VERSION 5.8 ;
BUSBITCHARS "[]" ;
DIVIDERCHAR "/" ;
UNITS
    DATABASE MICRONS 1000 ;
END UNITS

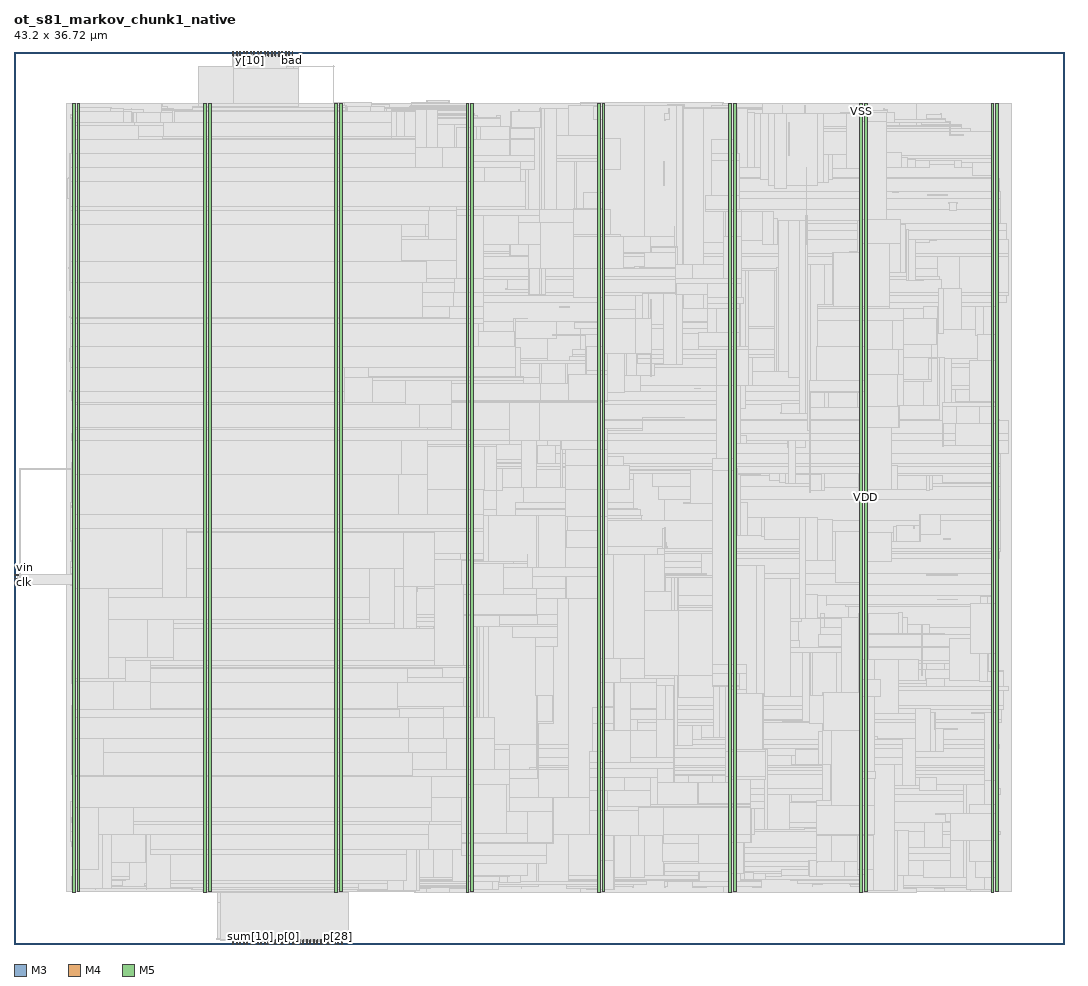
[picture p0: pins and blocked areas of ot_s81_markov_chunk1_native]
MACRO ot_s81_markov_chunk1_native
  FOREIGN ot_s81_markov_chunk1_native 0 0 ;
  CLASS BLOCK ;
  SIZE 43.2 BY 36.72 ;
  PIN bad
    DIRECTION OUTPUT ;
    USE SIGNAL ;
    PORT
      LAYER M3 ;
        RECT  11.448 36.576 11.466 36.72 ;
    END
  END bad
  PIN clk
    DIRECTION INPUT ;
    USE SIGNAL ;
    PORT
      LAYER M4 ;
        RECT  0 14.88 0.192 14.904 ;
    END
  END clk
  PIN p[0]
    DIRECTION INPUT ;
    USE SIGNAL ;
    PORT
      LAYER M3 ;
        RECT  11.304 0 11.322 0.144 ;
    END
  END p[0]
  PIN p[10]
    DIRECTION INPUT ;
    USE SIGNAL ;
    PORT
      LAYER M3 ;
        RECT  12.024 0 12.042 0.144 ;
    END
  END p[10]
  PIN p[11]
    DIRECTION INPUT ;
    USE SIGNAL ;
    PORT
      LAYER M5 ;
        RECT  12.048 0 12.072 0.192 ;
    END
  END p[11]
  PIN p[12]
    DIRECTION INPUT ;
    USE SIGNAL ;
    PORT
      LAYER M3 ;
        RECT  12.168 0 12.186 0.144 ;
    END
  END p[12]
  PIN p[13]
    DIRECTION INPUT ;
    USE SIGNAL ;
    PORT
      LAYER M5 ;
        RECT  12.192 0 12.216 0.192 ;
    END
  END p[13]
  PIN p[14]
    DIRECTION INPUT ;
    USE SIGNAL ;
    PORT
      LAYER M3 ;
        RECT  12.312 0 12.33 0.144 ;
    END
  END p[14]
  PIN p[15]
    DIRECTION INPUT ;
    USE SIGNAL ;
    PORT
      LAYER M5 ;
        RECT  12.336 0 12.36 0.192 ;
    END
  END p[15]
  PIN p[16]
    DIRECTION INPUT ;
    USE SIGNAL ;
    PORT
      LAYER M3 ;
        RECT  12.456 0 12.474 0.144 ;
    END
  END p[16]
  PIN p[17]
    DIRECTION INPUT ;
    USE SIGNAL ;
    PORT
      LAYER M5 ;
        RECT  12.48 0 12.504 0.192 ;
    END
  END p[17]
  PIN p[18]
    DIRECTION INPUT ;
    USE SIGNAL ;
    PORT
      LAYER M3 ;
        RECT  12.6 0 12.618 0.144 ;
    END
  END p[18]
  PIN p[19]
    DIRECTION INPUT ;
    USE SIGNAL ;
    PORT
      LAYER M5 ;
        RECT  12.624 0 12.648 0.192 ;
    END
  END p[19]
  PIN p[1]
    DIRECTION INPUT ;
    USE SIGNAL ;
    PORT
      LAYER M5 ;
        RECT  11.328 0 11.352 0.192 ;
    END
  END p[1]
  PIN p[20]
    DIRECTION INPUT ;
    USE SIGNAL ;
    PORT
      LAYER M3 ;
        RECT  12.744 0 12.762 0.144 ;
    END
  END p[20]
  PIN p[21]
    DIRECTION INPUT ;
    USE SIGNAL ;
    PORT
      LAYER M5 ;
        RECT  12.768 0 12.792 0.192 ;
    END
  END p[21]
  PIN p[22]
    DIRECTION INPUT ;
    USE SIGNAL ;
    PORT
      LAYER M3 ;
        RECT  12.888 0 12.906 0.144 ;
    END
  END p[22]
  PIN p[23]
    DIRECTION INPUT ;
    USE SIGNAL ;
    PORT
      LAYER M5 ;
        RECT  12.912 0 12.936 0.192 ;
    END
  END p[23]
  PIN p[24]
    DIRECTION INPUT ;
    USE SIGNAL ;
    PORT
      LAYER M3 ;
        RECT  13.032 0 13.05 0.144 ;
    END
  END p[24]
  PIN p[25]
    DIRECTION INPUT ;
    USE SIGNAL ;
    PORT
      LAYER M5 ;
        RECT  13.056 0 13.08 0.192 ;
    END
  END p[25]
  PIN p[26]
    DIRECTION INPUT ;
    USE SIGNAL ;
    PORT
      LAYER M3 ;
        RECT  13.176 0 13.194 0.144 ;
    END
  END p[26]
  PIN p[27]
    DIRECTION INPUT ;
    USE SIGNAL ;
    PORT
      LAYER M5 ;
        RECT  13.2 0 13.224 0.192 ;
    END
  END p[27]
  PIN p[28]
    DIRECTION INPUT ;
    USE SIGNAL ;
    PORT
      LAYER M3 ;
        RECT  13.32 0 13.338 0.144 ;
    END
  END p[28]
  PIN p[29]
    DIRECTION INPUT ;
    USE SIGNAL ;
    PORT
      LAYER M5 ;
        RECT  13.344 0 13.368 0.192 ;
    END
  END p[29]
  PIN p[2]
    DIRECTION INPUT ;
    USE SIGNAL ;
    PORT
      LAYER M3 ;
        RECT  11.448 0 11.466 0.144 ;
    END
  END p[2]
  PIN p[30]
    DIRECTION INPUT ;
    USE SIGNAL ;
    PORT
      LAYER M3 ;
        RECT  13.464 0 13.482 0.144 ;
    END
  END p[30]
  PIN p[31]
    DIRECTION INPUT ;
    USE SIGNAL ;
    PORT
      LAYER M5 ;
        RECT  13.488 0 13.512 0.192 ;
    END
  END p[31]
  PIN p[3]
    DIRECTION INPUT ;
    USE SIGNAL ;
    PORT
      LAYER M5 ;
        RECT  11.472 0 11.496 0.192 ;
    END
  END p[3]
  PIN p[4]
    DIRECTION INPUT ;
    USE SIGNAL ;
    PORT
      LAYER M3 ;
        RECT  11.592 0 11.61 0.144 ;
    END
  END p[4]
  PIN p[5]
    DIRECTION INPUT ;
    USE SIGNAL ;
    PORT
      LAYER M5 ;
        RECT  11.616 0 11.64 0.192 ;
    END
  END p[5]
  PIN p[6]
    DIRECTION INPUT ;
    USE SIGNAL ;
    PORT
      LAYER M3 ;
        RECT  11.736 0 11.754 0.144 ;
    END
  END p[6]
  PIN p[7]
    DIRECTION INPUT ;
    USE SIGNAL ;
    PORT
      LAYER M5 ;
        RECT  11.76 0 11.784 0.192 ;
    END
  END p[7]
  PIN p[8]
    DIRECTION INPUT ;
    USE SIGNAL ;
    PORT
      LAYER M3 ;
        RECT  11.88 0 11.898 0.144 ;
    END
  END p[8]
  PIN p[9]
    DIRECTION INPUT ;
    USE SIGNAL ;
    PORT
      LAYER M5 ;
        RECT  11.904 0 11.928 0.192 ;
    END
  END p[9]
  PIN rst_n
    DIRECTION INPUT ;
    USE SIGNAL ;
    PORT
      LAYER M4 ;
        RECT  0 15.024 0.192 15.048 ;
    END
  END rst_n
  PIN sum[0]
    DIRECTION INPUT ;
    USE SIGNAL ;
    PORT
      LAYER M3 ;
        RECT  9 0 9.018 0.144 ;
    END
  END sum[0]
  PIN sum[10]
    DIRECTION INPUT ;
    USE SIGNAL ;
    PORT
      LAYER M3 ;
        RECT  9.72 0 9.738 0.144 ;
    END
  END sum[10]
  PIN sum[11]
    DIRECTION INPUT ;
    USE SIGNAL ;
    PORT
      LAYER M5 ;
        RECT  9.744 0 9.768 0.192 ;
    END
  END sum[11]
  PIN sum[12]
    DIRECTION INPUT ;
    USE SIGNAL ;
    PORT
      LAYER M3 ;
        RECT  9.864 0 9.882 0.144 ;
    END
  END sum[12]
  PIN sum[13]
    DIRECTION INPUT ;
    USE SIGNAL ;
    PORT
      LAYER M5 ;
        RECT  9.888 0 9.912 0.192 ;
    END
  END sum[13]
  PIN sum[14]
    DIRECTION INPUT ;
    USE SIGNAL ;
    PORT
      LAYER M3 ;
        RECT  10.008 0 10.026 0.144 ;
    END
  END sum[14]
  PIN sum[15]
    DIRECTION INPUT ;
    USE SIGNAL ;
    PORT
      LAYER M5 ;
        RECT  10.032 0 10.056 0.192 ;
    END
  END sum[15]
  PIN sum[16]
    DIRECTION INPUT ;
    USE SIGNAL ;
    PORT
      LAYER M3 ;
        RECT  10.152 0 10.17 0.144 ;
    END
  END sum[16]
  PIN sum[17]
    DIRECTION INPUT ;
    USE SIGNAL ;
    PORT
      LAYER M5 ;
        RECT  10.176 0 10.2 0.192 ;
    END
  END sum[17]
  PIN sum[18]
    DIRECTION INPUT ;
    USE SIGNAL ;
    PORT
      LAYER M3 ;
        RECT  10.296 0 10.314 0.144 ;
    END
  END sum[18]
  PIN sum[19]
    DIRECTION INPUT ;
    USE SIGNAL ;
    PORT
      LAYER M5 ;
        RECT  10.32 0 10.344 0.192 ;
    END
  END sum[19]
  PIN sum[1]
    DIRECTION INPUT ;
    USE SIGNAL ;
    PORT
      LAYER M5 ;
        RECT  9.024 0 9.048 0.192 ;
    END
  END sum[1]
  PIN sum[20]
    DIRECTION INPUT ;
    USE SIGNAL ;
    PORT
      LAYER M3 ;
        RECT  10.44 0 10.458 0.144 ;
    END
  END sum[20]
  PIN sum[21]
    DIRECTION INPUT ;
    USE SIGNAL ;
    PORT
      LAYER M5 ;
        RECT  10.464 0 10.488 0.192 ;
    END
  END sum[21]
  PIN sum[22]
    DIRECTION INPUT ;
    USE SIGNAL ;
    PORT
      LAYER M3 ;
        RECT  10.584 0 10.602 0.144 ;
    END
  END sum[22]
  PIN sum[23]
    DIRECTION INPUT ;
    USE SIGNAL ;
    PORT
      LAYER M5 ;
        RECT  10.608 0 10.632 0.192 ;
    END
  END sum[23]
  PIN sum[24]
    DIRECTION INPUT ;
    USE SIGNAL ;
    PORT
      LAYER M3 ;
        RECT  10.728 0 10.746 0.144 ;
    END
  END sum[24]
  PIN sum[25]
    DIRECTION INPUT ;
    USE SIGNAL ;
    PORT
      LAYER M5 ;
        RECT  10.752 0 10.776 0.192 ;
    END
  END sum[25]
  PIN sum[26]
    DIRECTION INPUT ;
    USE SIGNAL ;
    PORT
      LAYER M3 ;
        RECT  10.872 0 10.89 0.144 ;
    END
  END sum[26]
  PIN sum[27]
    DIRECTION INPUT ;
    USE SIGNAL ;
    PORT
      LAYER M5 ;
        RECT  10.896 0 10.92 0.192 ;
    END
  END sum[27]
  PIN sum[28]
    DIRECTION INPUT ;
    USE SIGNAL ;
    PORT
      LAYER M3 ;
        RECT  11.016 0 11.034 0.144 ;
    END
  END sum[28]
  PIN sum[29]
    DIRECTION INPUT ;
    USE SIGNAL ;
    PORT
      LAYER M5 ;
        RECT  11.04 0 11.064 0.192 ;
    END
  END sum[29]
  PIN sum[2]
    DIRECTION INPUT ;
    USE SIGNAL ;
    PORT
      LAYER M3 ;
        RECT  9.144 0 9.162 0.144 ;
    END
  END sum[2]
  PIN sum[30]
    DIRECTION INPUT ;
    USE SIGNAL ;
    PORT
      LAYER M3 ;
        RECT  11.16 0 11.178 0.144 ;
    END
  END sum[30]
  PIN sum[31]
    DIRECTION INPUT ;
    USE SIGNAL ;
    PORT
      LAYER M5 ;
        RECT  11.184 0 11.208 0.192 ;
    END
  END sum[31]
  PIN sum[3]
    DIRECTION INPUT ;
    USE SIGNAL ;
    PORT
      LAYER M5 ;
        RECT  9.168 0 9.192 0.192 ;
    END
  END sum[3]
  PIN sum[4]
    DIRECTION INPUT ;
    USE SIGNAL ;
    PORT
      LAYER M3 ;
        RECT  9.288 0 9.306 0.144 ;
    END
  END sum[4]
  PIN sum[5]
    DIRECTION INPUT ;
    USE SIGNAL ;
    PORT
      LAYER M5 ;
        RECT  9.312 0 9.336 0.192 ;
    END
  END sum[5]
  PIN sum[6]
    DIRECTION INPUT ;
    USE SIGNAL ;
    PORT
      LAYER M3 ;
        RECT  9.432 0 9.45 0.144 ;
    END
  END sum[6]
  PIN sum[7]
    DIRECTION INPUT ;
    USE SIGNAL ;
    PORT
      LAYER M5 ;
        RECT  9.456 0 9.48 0.192 ;
    END
  END sum[7]
  PIN sum[8]
    DIRECTION INPUT ;
    USE SIGNAL ;
    PORT
      LAYER M3 ;
        RECT  9.576 0 9.594 0.144 ;
    END
  END sum[8]
  PIN sum[9]
    DIRECTION INPUT ;
    USE SIGNAL ;
    PORT
      LAYER M5 ;
        RECT  9.6 0 9.624 0.192 ;
    END
  END sum[9]
  PIN vin
    DIRECTION INPUT ;
    USE SIGNAL ;
    PORT
      LAYER M4 ;
        RECT  0 15.168 0.192 15.192 ;
    END
  END vin
  PIN vout
    DIRECTION OUTPUT ;
    USE SIGNAL ;
    PORT
      LAYER M3 ;
        RECT  11.304 36.576 11.322 36.72 ;
    END
  END vout
  PIN y[0]
    DIRECTION OUTPUT ;
    USE SIGNAL ;
    PORT
      LAYER M3 ;
        RECT  9 36.576 9.018 36.72 ;
    END
  END y[0]
  PIN y[10]
    DIRECTION OUTPUT ;
    USE SIGNAL ;
    PORT
      LAYER M3 ;
        RECT  9.72 36.576 9.738 36.72 ;
    END
  END y[10]
  PIN y[11]
    DIRECTION OUTPUT ;
    USE SIGNAL ;
    PORT
      LAYER M5 ;
        RECT  9.744 36.528 9.768 36.72 ;
    END
  END y[11]
  PIN y[12]
    DIRECTION OUTPUT ;
    USE SIGNAL ;
    PORT
      LAYER M3 ;
        RECT  9.864 36.576 9.882 36.72 ;
    END
  END y[12]
  PIN y[13]
    DIRECTION OUTPUT ;
    USE SIGNAL ;
    PORT
      LAYER M5 ;
        RECT  9.888 36.528 9.912 36.72 ;
    END
  END y[13]
  PIN y[14]
    DIRECTION OUTPUT ;
    USE SIGNAL ;
    PORT
      LAYER M3 ;
        RECT  10.008 36.576 10.026 36.72 ;
    END
  END y[14]
  PIN y[15]
    DIRECTION OUTPUT ;
    USE SIGNAL ;
    PORT
      LAYER M5 ;
        RECT  10.032 36.528 10.056 36.72 ;
    END
  END y[15]
  PIN y[16]
    DIRECTION OUTPUT ;
    USE SIGNAL ;
    PORT
      LAYER M3 ;
        RECT  10.152 36.576 10.17 36.72 ;
    END
  END y[16]
  PIN y[17]
    DIRECTION OUTPUT ;
    USE SIGNAL ;
    PORT
      LAYER M5 ;
        RECT  10.176 36.528 10.2 36.72 ;
    END
  END y[17]
  PIN y[18]
    DIRECTION OUTPUT ;
    USE SIGNAL ;
    PORT
      LAYER M3 ;
        RECT  10.296 36.576 10.314 36.72 ;
    END
  END y[18]
  PIN y[19]
    DIRECTION OUTPUT ;
    USE SIGNAL ;
    PORT
      LAYER M5 ;
        RECT  10.32 36.528 10.344 36.72 ;
    END
  END y[19]
  PIN y[1]
    DIRECTION OUTPUT ;
    USE SIGNAL ;
    PORT
      LAYER M5 ;
        RECT  9.024 36.528 9.048 36.72 ;
    END
  END y[1]
  PIN y[20]
    DIRECTION OUTPUT ;
    USE SIGNAL ;
    PORT
      LAYER M3 ;
        RECT  10.44 36.576 10.458 36.72 ;
    END
  END y[20]
  PIN y[21]
    DIRECTION OUTPUT ;
    USE SIGNAL ;
    PORT
      LAYER M5 ;
        RECT  10.464 36.528 10.488 36.72 ;
    END
  END y[21]
  PIN y[22]
    DIRECTION OUTPUT ;
    USE SIGNAL ;
    PORT
      LAYER M3 ;
        RECT  10.584 36.576 10.602 36.72 ;
    END
  END y[22]
  PIN y[23]
    DIRECTION OUTPUT ;
    USE SIGNAL ;
    PORT
      LAYER M5 ;
        RECT  10.608 36.528 10.632 36.72 ;
    END
  END y[23]
  PIN y[24]
    DIRECTION OUTPUT ;
    USE SIGNAL ;
    PORT
      LAYER M3 ;
        RECT  10.728 36.576 10.746 36.72 ;
    END
  END y[24]
  PIN y[25]
    DIRECTION OUTPUT ;
    USE SIGNAL ;
    PORT
      LAYER M5 ;
        RECT  10.752 36.528 10.776 36.72 ;
    END
  END y[25]
  PIN y[26]
    DIRECTION OUTPUT ;
    USE SIGNAL ;
    PORT
      LAYER M3 ;
        RECT  10.872 36.576 10.89 36.72 ;
    END
  END y[26]
  PIN y[27]
    DIRECTION OUTPUT ;
    USE SIGNAL ;
    PORT
      LAYER M5 ;
        RECT  10.896 36.528 10.92 36.72 ;
    END
  END y[27]
  PIN y[28]
    DIRECTION OUTPUT ;
    USE SIGNAL ;
    PORT
      LAYER M3 ;
        RECT  11.016 36.576 11.034 36.72 ;
    END
  END y[28]
  PIN y[29]
    DIRECTION OUTPUT ;
    USE SIGNAL ;
    PORT
      LAYER M5 ;
        RECT  11.04 36.528 11.064 36.72 ;
    END
  END y[29]
  PIN y[2]
    DIRECTION OUTPUT ;
    USE SIGNAL ;
    PORT
      LAYER M3 ;
        RECT  9.144 36.576 9.162 36.72 ;
    END
  END y[2]
  PIN y[30]
    DIRECTION OUTPUT ;
    USE SIGNAL ;
    PORT
      LAYER M3 ;
        RECT  11.16 36.576 11.178 36.72 ;
    END
  END y[30]
  PIN y[31]
    DIRECTION OUTPUT ;
    USE SIGNAL ;
    PORT
      LAYER M5 ;
        RECT  11.184 36.528 11.208 36.72 ;
    END
  END y[31]
  PIN y[3]
    DIRECTION OUTPUT ;
    USE SIGNAL ;
    PORT
      LAYER M5 ;
        RECT  9.168 36.528 9.192 36.72 ;
    END
  END y[3]
  PIN y[4]
    DIRECTION OUTPUT ;
    USE SIGNAL ;
    PORT
      LAYER M3 ;
        RECT  9.288 36.576 9.306 36.72 ;
    END
  END y[4]
  PIN y[5]
    DIRECTION OUTPUT ;
    USE SIGNAL ;
    PORT
      LAYER M5 ;
        RECT  9.312 36.528 9.336 36.72 ;
    END
  END y[5]
  PIN y[6]
    DIRECTION OUTPUT ;
    USE SIGNAL ;
    PORT
      LAYER M3 ;
        RECT  9.432 36.576 9.45 36.72 ;
    END
  END y[6]
  PIN y[7]
    DIRECTION OUTPUT ;
    USE SIGNAL ;
    PORT
      LAYER M5 ;
        RECT  9.456 36.528 9.48 36.72 ;
    END
  END y[7]
  PIN y[8]
    DIRECTION OUTPUT ;
    USE SIGNAL ;
    PORT
      LAYER M3 ;
        RECT  9.576 36.576 9.594 36.72 ;
    END
  END y[8]
  PIN y[9]
    DIRECTION OUTPUT ;
    USE SIGNAL ;
    PORT
      LAYER M5 ;
        RECT  9.6 36.528 9.624 36.72 ;
    END
  END y[9]
  PIN VDD
    DIRECTION INOUT ;
    USE POWER ;
    PORT
      LAYER M5 ;
        RECT  40.392 2.151 40.512 34.569 ;
        RECT  34.992 2.151 35.112 34.569 ;
        RECT  29.592 2.151 29.712 34.569 ;
        RECT  24.192 2.151 24.312 34.569 ;
        RECT  18.792 2.151 18.912 34.569 ;
        RECT  13.392 2.151 13.512 34.569 ;
        RECT  7.992 2.151 8.112 34.569 ;
        RECT  2.592 2.151 2.712 34.569 ;
    END
  END VDD
  PIN VSS
    DIRECTION INOUT ;
    USE GROUND ;
    PORT
      LAYER M5 ;
        RECT  40.2 2.137 40.32 34.583 ;
        RECT  34.8 2.137 34.92 34.583 ;
        RECT  29.4 2.137 29.52 34.583 ;
        RECT  24 2.137 24.12 34.583 ;
        RECT  18.6 2.137 18.72 34.583 ;
        RECT  13.2 2.137 13.32 34.583 ;
        RECT  7.8 2.137 7.92 34.583 ;
        RECT  2.4 2.137 2.52 34.583 ;
    END
  END VSS
  # OT_OBS_CLOSED layer=M5 d_um=1.536 added=148
  OBS
    LAYER RVTN ;
     RECT  2.16 2.16 41.04 2.295 ;
     RECT  2.16 2.565 41.04 2.835 ;
     RECT  2.16 3.105 41.04 3.375 ;
     RECT  2.16 3.645 41.04 3.915 ;
     RECT  2.16 4.185 41.04 4.455 ;
     RECT  2.16 4.725 41.04 4.995 ;
     RECT  2.16 5.265 41.04 5.535 ;
     RECT  2.16 5.805 41.04 6.075 ;
     RECT  2.16 6.345 41.04 6.615 ;
     RECT  2.16 6.885 41.04 7.155 ;
     RECT  2.16 7.425 41.04 7.695 ;
     RECT  2.16 7.965 41.04 8.235 ;
     RECT  2.16 8.505 41.04 8.775 ;
     RECT  2.16 9.045 41.04 9.315 ;
     RECT  2.16 9.585 41.04 9.855 ;
     RECT  2.16 10.125 41.04 10.395 ;
     RECT  2.16 10.665 41.04 10.935 ;
     RECT  2.16 11.205 41.04 11.475 ;
     RECT  2.16 11.745 41.04 12.015 ;
     RECT  2.16 12.285 41.04 12.555 ;
     RECT  2.16 12.825 41.04 13.095 ;
     RECT  2.16 13.365 41.04 13.635 ;
     RECT  2.16 13.905 41.04 14.175 ;
     RECT  2.16 14.445 41.04 14.715 ;
     RECT  2.16 14.985 41.04 15.255 ;
     RECT  2.16 15.525 41.04 15.795 ;
     RECT  2.16 16.065 41.04 16.335 ;
     RECT  2.16 16.605 41.04 16.875 ;
     RECT  2.16 17.145 41.04 17.415 ;
     RECT  2.16 17.685 41.04 17.955 ;
     RECT  2.16 18.225 41.04 18.495 ;
     RECT  2.16 18.765 41.04 19.035 ;
     RECT  2.16 19.305 41.04 19.575 ;
     RECT  2.16 19.845 41.04 20.115 ;
     RECT  2.16 20.385 41.04 20.655 ;
     RECT  2.16 20.925 41.04 21.195 ;
     RECT  2.16 21.465 41.04 21.735 ;
     RECT  2.16 22.005 41.04 22.275 ;
     RECT  2.16 22.545 41.04 22.815 ;
     RECT  2.16 23.085 41.04 23.355 ;
     RECT  2.16 23.625 41.04 23.895 ;
     RECT  2.16 24.165 41.04 24.435 ;
     RECT  2.16 24.705 41.04 24.975 ;
     RECT  2.16 25.245 41.04 25.515 ;
     RECT  2.16 25.785 41.04 26.055 ;
     RECT  2.16 26.325 41.04 26.595 ;
     RECT  2.16 26.865 41.04 27.135 ;
     RECT  2.16 27.405 41.04 27.675 ;
     RECT  2.16 27.945 41.04 28.215 ;
     RECT  2.16 28.485 41.04 28.755 ;
     RECT  2.16 29.025 41.04 29.295 ;
     RECT  2.16 29.565 41.04 29.835 ;
     RECT  2.16 30.105 41.04 30.375 ;
     RECT  2.16 30.645 41.04 30.915 ;
     RECT  2.16 31.185 41.04 31.455 ;
     RECT  2.16 31.725 41.04 31.995 ;
     RECT  2.16 32.265 41.04 32.535 ;
     RECT  2.16 32.805 41.04 33.075 ;
     RECT  2.16 33.345 41.04 33.615 ;
     RECT  2.16 33.885 41.04 34.155 ;
     RECT  2.16 34.425 41.04 34.56 ;
    LAYER RVTP ;
     RECT  2.16 2.295 41.04 2.565 ;
     RECT  2.16 2.835 41.04 3.105 ;
     RECT  2.16 3.375 41.04 3.645 ;
     RECT  2.16 3.915 41.04 4.185 ;
     RECT  2.16 4.455 41.04 4.725 ;
     RECT  2.16 4.995 41.04 5.265 ;
     RECT  2.16 5.535 41.04 5.805 ;
     RECT  2.16 6.075 41.04 6.345 ;
     RECT  2.16 6.615 41.04 6.885 ;
     RECT  2.16 7.155 41.04 7.425 ;
     RECT  2.16 7.695 41.04 7.965 ;
     RECT  2.16 8.235 41.04 8.505 ;
     RECT  2.16 8.775 41.04 9.045 ;
     RECT  2.16 9.315 41.04 9.585 ;
     RECT  2.16 9.855 41.04 10.125 ;
     RECT  2.16 10.395 41.04 10.665 ;
     RECT  2.16 10.935 41.04 11.205 ;
     RECT  2.16 11.475 41.04 11.745 ;
     RECT  2.16 12.015 41.04 12.285 ;
     RECT  2.16 12.555 41.04 12.825 ;
     RECT  2.16 13.095 41.04 13.365 ;
     RECT  2.16 13.635 41.04 13.905 ;
     RECT  2.16 14.175 41.04 14.445 ;
     RECT  2.16 14.715 41.04 14.985 ;
     RECT  2.16 15.255 41.04 15.525 ;
     RECT  2.16 15.795 41.04 16.065 ;
     RECT  2.16 16.335 41.04 16.605 ;
     RECT  2.16 16.875 41.04 17.145 ;
     RECT  2.16 17.415 41.04 17.685 ;
     RECT  2.16 17.955 41.04 18.225 ;
     RECT  2.16 18.495 41.04 18.765 ;
     RECT  2.16 19.035 41.04 19.305 ;
     RECT  2.16 19.575 41.04 19.845 ;
     RECT  2.16 20.115 41.04 20.385 ;
     RECT  2.16 20.655 41.04 20.925 ;
     RECT  2.16 21.195 41.04 21.465 ;
     RECT  2.16 21.735 41.04 22.005 ;
     RECT  2.16 22.275 41.04 22.545 ;
     RECT  2.16 22.815 41.04 23.085 ;
     RECT  2.16 23.355 41.04 23.625 ;
     RECT  2.16 23.895 41.04 24.165 ;
     RECT  2.16 24.435 41.04 24.705 ;
     RECT  2.16 24.975 41.04 25.245 ;
     RECT  2.16 25.515 41.04 25.785 ;
     RECT  2.16 26.055 41.04 26.325 ;
     RECT  2.16 26.595 41.04 26.865 ;
     RECT  2.16 27.135 41.04 27.405 ;
     RECT  2.16 27.675 41.04 27.945 ;
     RECT  2.16 28.215 41.04 28.485 ;
     RECT  2.16 28.755 41.04 29.025 ;
     RECT  2.16 29.295 41.04 29.565 ;
     RECT  2.16 29.835 41.04 30.105 ;
     RECT  2.16 30.375 41.04 30.645 ;
     RECT  2.16 30.915 41.04 31.185 ;
     RECT  2.16 31.455 41.04 31.725 ;
     RECT  2.16 31.995 41.04 32.265 ;
     RECT  2.16 32.535 41.04 32.805 ;
     RECT  2.16 33.075 41.04 33.345 ;
     RECT  2.16 33.615 41.04 33.885 ;
     RECT  2.16 34.155 41.04 34.425 ;
    LAYER M1 ;
     RECT  2.16 2.151 41.04 34.569 ;
    LAYER M2 ;
     RECT  2.16 2.151 8.203 34.569 ;
     RECT  8.203 2.106 9.355 34.569 ;
     RECT  9.355 1.728 9.463 34.569 ;
     RECT  9.463 1.728 9.599 34.794 ;
     RECT  9.599 1.728 9.815 34.569 ;
     RECT  9.815 2.151 10.579 34.569 ;
     RECT  10.579 0.144 10.679 0.162 ;
     RECT  10.579 2.151 10.823 34.794 ;
     RECT  12.163 0.144 12.883 0.162 ;
     RECT  12.883 0.144 12.983 0.63 ;
     RECT  12.983 0.144 13.487 0.162 ;
     RECT  10.823 2.151 13.567 34.569 ;
     RECT  13.567 2.151 14.711 34.614 ;
     RECT  14.711 2.151 16.339 34.569 ;
     RECT  16.339 2.151 16.483 34.614 ;
     RECT  16.483 2.106 16.987 34.614 ;
     RECT  16.987 2.106 17.915 34.686 ;
     RECT  17.915 2.106 23.323 34.569 ;
     RECT  23.323 2.106 29.183 34.614 ;
     RECT  29.183 2.106 37.139 34.569 ;
     RECT  37.139 2.151 41.04 34.569 ;
    LAYER M3 ;
     RECT  9 0.108 13.482 0.167 ;
     RECT  9 0.167 13.41 0.187 ;
     RECT  8.352 0.187 13.41 1.723 ;
     RECT  8.352 1.723 13.662 2.101 ;
     RECT  8.208 2.101 13.662 2.143 ;
     RECT  7.815 2.143 13.662 2.155 ;
     RECT  7.815 2.155 13.914 2.191 ;
     RECT  16.488 2.101 16.506 2.191 ;
     RECT  34.815 2.143 34.905 2.191 ;
     RECT  40.215 2.143 40.305 2.191 ;
     RECT  16.2 2.191 16.506 2.203 ;
     RECT  2.415 2.143 2.505 2.227 ;
     RECT  15.516 2.203 16.686 2.227 ;
     RECT  24.015 2.143 24.105 2.227 ;
     RECT  34.815 2.191 35.442 2.227 ;
     RECT  36.324 2.203 36.342 2.227 ;
     RECT  7.74 2.191 14.634 2.251 ;
     RECT  39.348 2.191 39.366 2.251 ;
     RECT  40.176 2.191 40.305 2.251 ;
     RECT  34.815 2.227 36.342 2.255 ;
     RECT  15.372 2.227 16.686 2.263 ;
     RECT  18.615 2.143 18.705 2.263 ;
     RECT  23.544 2.227 24.678 2.263 ;
     RECT  37.116 2.101 37.134 2.263 ;
     RECT  38.268 2.191 38.286 2.263 ;
     RECT  7.308 2.251 14.634 2.299 ;
     RECT  15.372 2.263 17.118 2.335 ;
     RECT  17.964 2.263 18.705 2.335 ;
     RECT  36.612 2.263 37.134 2.335 ;
     RECT  37.872 2.263 38.286 2.335 ;
     RECT  39.204 2.251 40.305 2.335 ;
     RECT  4.428 2.299 4.446 2.347 ;
     RECT  5.436 2.227 5.454 2.347 ;
     RECT  6.624 2.299 14.634 2.347 ;
     RECT  3.348 2.227 3.366 2.371 ;
     RECT  4.248 2.347 4.446 2.371 ;
     RECT  5.364 2.347 5.454 2.371 ;
     RECT  6.3 2.347 14.634 2.371 ;
     RECT  15.372 2.335 18.705 2.371 ;
     RECT  19.908 2.227 19.926 2.371 ;
     RECT  20.88 2.299 20.898 2.371 ;
     RECT  22.716 2.263 24.678 2.371 ;
     RECT  25.452 2.335 25.47 2.371 ;
     RECT  26.784 2.335 26.802 2.371 ;
     RECT  27.9 2.335 28.494 2.371 ;
     RECT  29.415 2.143 29.505 2.371 ;
     RECT  30.384 2.335 30.762 2.371 ;
     RECT  34.815 2.255 35.766 2.371 ;
     RECT  2.376 2.227 2.505 2.413 ;
     RECT  3.348 2.371 4.446 2.413 ;
     RECT  5.364 2.371 18.705 2.413 ;
     RECT  36.612 2.335 40.305 2.413 ;
     RECT  19.908 2.371 21.582 2.461 ;
     RECT  22.716 2.371 25.47 2.461 ;
     RECT  32.832 2.371 32.85 2.461 ;
     RECT  34.416 2.371 35.766 2.461 ;
     RECT  5.364 2.413 18.897 2.489 ;
     RECT  32.832 2.461 33.246 2.497 ;
     RECT  34.38 2.461 35.766 2.497 ;
     RECT  26.784 2.371 26.874 2.569 ;
     RECT  27.9 2.371 30.762 2.569 ;
     RECT  5.472 2.489 18.897 2.587 ;
     RECT  19.908 2.461 26.01 2.587 ;
     RECT  2.376 2.413 4.446 2.605 ;
     RECT  5.472 2.587 26.01 2.605 ;
     RECT  26.784 2.569 30.762 2.605 ;
     RECT  32.256 2.497 35.766 2.605 ;
     RECT  5.472 2.605 30.762 2.635 ;
     RECT  2.376 2.605 4.59 2.641 ;
     RECT  5.472 2.635 30.906 2.641 ;
     RECT  31.932 2.605 35.766 2.641 ;
     RECT  2.376 2.641 4.734 2.759 ;
     RECT  5.472 2.641 35.766 3.001 ;
     RECT  5.472 3.001 35.802 3.181 ;
     RECT  36.612 2.413 40.497 3.181 ;
     RECT  2.415 2.759 4.734 3.379 ;
     RECT  5.472 3.181 40.497 3.379 ;
     RECT  2.415 3.379 40.497 3.725 ;
     RECT  5.904 3.725 40.497 3.983 ;
     RECT  2.415 3.725 5.166 3.991 ;
     RECT  2.376 3.991 5.166 4.225 ;
     RECT  38.196 3.983 40.497 4.495 ;
     RECT  2.34 4.225 5.166 4.621 ;
     RECT  5.904 3.983 37.458 4.621 ;
     RECT  38.196 4.495 40.59 4.649 ;
     RECT  2.34 4.621 37.458 4.999 ;
     RECT  38.196 4.649 40.497 4.999 ;
     RECT  2.34 4.999 40.497 5.873 ;
     RECT  2.415 5.873 40.497 6.151 ;
     RECT  2.415 6.151 40.59 6.413 ;
     RECT  2.415 6.413 40.497 6.961 ;
     RECT  2.376 6.961 40.497 7.133 ;
     RECT  21.132 7.133 40.497 7.151 ;
     RECT  21.204 7.151 40.497 7.259 ;
     RECT  21.492 7.259 40.497 7.349 ;
     RECT  21.528 7.349 40.497 7.655 ;
     RECT  2.376 7.133 20.394 7.997 ;
     RECT  21.564 7.655 40.497 8.041 ;
     RECT  21.564 8.041 40.554 8.195 ;
     RECT  2.376 7.997 8.55 8.231 ;
     RECT  9.288 7.997 20.394 8.311 ;
     RECT  21.564 8.195 40.497 8.429 ;
     RECT  9.288 8.311 20.61 8.473 ;
     RECT  9.288 8.473 20.682 8.851 ;
     RECT  21.564 8.429 24.93 8.851 ;
     RECT  2.376 8.231 8.478 9.019 ;
     RECT  9.288 8.851 24.93 9.019 ;
     RECT  25.668 8.429 40.497 9.121 ;
     RECT  2.376 9.019 24.93 9.247 ;
     RECT  25.668 9.121 40.626 9.247 ;
     RECT  2.376 9.247 40.626 9.661 ;
     RECT  2.376 9.661 40.698 9.815 ;
     RECT  2.415 9.815 40.698 10.435 ;
     RECT  2.415 10.435 40.914 10.589 ;
     RECT  2.415 10.589 37.53 10.705 ;
     RECT  38.268 10.589 40.698 11.261 ;
     RECT  2.376 10.705 37.53 11.551 ;
     RECT  38.268 11.261 40.497 11.551 ;
     RECT  2.376 11.551 40.497 11.669 ;
     RECT  2.415 11.669 40.497 12.209 ;
     RECT  33.084 12.209 40.497 12.245 ;
     RECT  2.415 12.209 32.31 12.479 ;
     RECT  33.12 12.245 40.497 12.749 ;
     RECT  33.192 12.749 40.497 13.019 ;
     RECT  2.415 12.479 32.274 13.261 ;
     RECT  2.415 13.261 32.418 13.433 ;
     RECT  2.415 13.433 32.274 13.559 ;
     RECT  33.192 13.019 33.354 13.595 ;
     RECT  24.015 13.559 32.274 13.829 ;
     RECT  34.344 13.019 40.497 13.873 ;
     RECT  25.668 13.829 32.274 13.937 ;
     RECT  33.408 13.945 33.426 13.981 ;
     RECT  34.2 13.873 40.497 13.981 ;
     RECT  31.356 13.937 32.274 14.215 ;
     RECT  31.356 14.215 32.454 14.347 ;
     RECT  33.408 13.981 40.497 14.347 ;
     RECT  25.668 13.937 30.474 14.441 ;
     RECT  2.415 13.559 23.238 14.755 ;
     RECT  24.015 13.829 24.894 14.755 ;
     RECT  25.668 14.441 29.97 14.755 ;
     RECT  2.34 14.755 23.238 14.791 ;
     RECT  31.356 14.347 40.497 14.791 ;
     RECT  2.304 14.791 23.238 14.881 ;
     RECT  24.015 14.755 29.97 14.881 ;
     RECT  2.304 14.881 29.97 15.163 ;
     RECT  2.268 15.163 29.97 15.179 ;
     RECT  2.268 15.179 28.494 15.215 ;
     RECT  29.232 15.179 29.97 15.223 ;
     RECT  30.78 14.791 40.497 15.223 ;
     RECT  2.304 15.215 28.494 15.251 ;
     RECT  2.304 15.251 28.278 15.485 ;
     RECT  2.34 15.485 28.278 15.719 ;
     RECT  29.232 15.223 40.497 15.871 ;
     RECT  2.376 15.719 28.278 16.069 ;
     RECT  29.232 15.871 40.554 16.069 ;
     RECT  2.376 16.069 40.554 16.141 ;
     RECT  2.376 16.141 40.59 16.259 ;
     RECT  2.376 16.259 11.466 16.439 ;
     RECT  2.376 16.439 11.286 16.555 ;
     RECT  2.34 16.555 11.286 16.601 ;
     RECT  6.228 16.601 11.286 16.907 ;
     RECT  6.3 16.907 11.286 17.249 ;
     RECT  12.24 16.259 40.59 17.411 ;
     RECT  12.24 17.411 25.83 17.491 ;
     RECT  12.132 17.491 25.83 17.501 ;
     RECT  12.132 17.501 19.854 17.581 ;
     RECT  20.628 17.501 25.83 17.645 ;
     RECT  11.988 17.581 19.854 17.879 ;
     RECT  20.628 17.645 25.794 17.879 ;
     RECT  20.628 17.879 25.65 17.915 ;
     RECT  2.34 16.601 5.49 17.947 ;
     RECT  6.3 17.249 11.106 17.947 ;
     RECT  2.34 17.947 11.106 17.995 ;
     RECT  2.34 17.995 11.214 18.031 ;
     RECT  11.988 17.879 16.722 18.031 ;
     RECT  2.34 18.031 16.722 18.149 ;
     RECT  20.628 17.915 25.47 18.149 ;
     RECT  2.376 18.149 16.65 18.221 ;
     RECT  26.748 17.411 40.59 18.301 ;
     RECT  2.376 18.221 16.254 18.599 ;
     RECT  17.532 17.879 19.854 18.661 ;
     RECT  2.376 18.599 11.718 18.749 ;
     RECT  26.532 18.301 40.59 18.841 ;
     RECT  17.532 18.661 20.07 18.967 ;
     RECT  17.532 18.967 20.178 19.039 ;
     RECT  12.492 18.599 16.254 19.111 ;
     RECT  17.064 19.039 20.178 19.111 ;
     RECT  20.952 18.149 25.47 19.111 ;
     RECT  2.415 18.749 11.718 19.345 ;
     RECT  12.492 19.111 25.47 19.345 ;
     RECT  26.28 18.841 40.59 19.345 ;
     RECT  2.415 19.345 40.59 19.651 ;
     RECT  2.376 19.651 40.59 19.769 ;
     RECT  2.376 19.769 21.546 19.805 ;
     RECT  2.415 19.805 21.546 19.949 ;
     RECT  22.284 19.769 40.59 20.191 ;
     RECT  2.415 19.949 10.926 20.695 ;
     RECT  11.736 19.949 21.546 20.695 ;
     RECT  2.415 20.695 21.546 20.731 ;
     RECT  22.284 20.191 40.914 20.731 ;
     RECT  2.376 20.731 40.914 20.993 ;
     RECT  2.415 20.993 40.914 21.533 ;
     RECT  2.415 21.533 40.554 21.569 ;
     RECT  2.415 21.569 40.497 22.205 ;
     RECT  2.415 22.205 32.49 22.351 ;
     RECT  2.376 22.351 32.49 22.733 ;
     RECT  2.376 22.733 24.822 22.783 ;
     RECT  25.776 22.733 32.49 22.987 ;
     RECT  33.228 22.205 40.497 22.987 ;
     RECT  25.776 22.987 40.497 23.701 ;
     RECT  2.34 22.783 24.822 23.999 ;
     RECT  25.632 23.701 40.497 24.089 ;
     RECT  2.34 23.999 21.942 24.091 ;
     RECT  22.86 23.999 24.822 24.161 ;
     RECT  22.968 24.161 24.822 24.241 ;
     RECT  25.632 24.089 33.246 24.241 ;
     RECT  22.968 24.241 33.246 24.461 ;
     RECT  22.968 24.461 33.21 24.467 ;
     RECT  2.304 24.091 21.942 24.907 ;
     RECT  23.292 24.467 33.21 25.321 ;
     RECT  23.076 25.321 33.21 25.555 ;
     RECT  34.236 24.089 40.497 25.555 ;
     RECT  2.304 24.907 22.302 25.591 ;
     RECT  23.076 25.555 40.497 25.591 ;
     RECT  2.304 25.591 40.497 26.401 ;
     RECT  2.304 26.401 40.842 26.671 ;
     RECT  2.304 26.671 40.914 26.789 ;
     RECT  2.304 26.789 38.178 27.329 ;
     RECT  2.304 27.329 38.07 27.473 ;
     RECT  2.304 27.473 37.998 27.787 ;
     RECT  2.268 27.787 37.998 28.291 ;
     RECT  38.916 26.789 40.914 28.291 ;
     RECT  2.268 28.291 40.914 28.409 ;
     RECT  28.008 28.409 40.914 28.985 ;
     RECT  2.268 28.409 27.018 29.219 ;
     RECT  2.34 29.219 27.018 29.261 ;
     RECT  5.796 29.261 27.018 29.335 ;
     RECT  28.008 28.985 40.842 29.335 ;
     RECT  5.796 29.335 40.842 29.633 ;
     RECT  2.34 29.261 5.058 29.933 ;
     RECT  2.376 29.933 5.058 30.235 ;
     RECT  5.796 29.633 40.59 30.235 ;
     RECT  2.376 30.235 40.59 30.667 ;
     RECT  2.232 30.667 40.59 30.947 ;
     RECT  2.232 30.947 40.554 31.487 ;
     RECT  2.232 31.487 40.497 31.517 ;
     RECT  2.34 31.517 40.497 32.299 ;
     RECT  2.304 32.299 40.497 32.459 ;
     RECT  2.376 32.459 40.497 33.449 ;
     RECT  2.376 33.449 39.366 33.539 ;
     RECT  2.376 33.539 38.97 33.629 ;
     RECT  20.772 33.629 38.97 33.683 ;
     RECT  37.332 33.683 38.97 33.719 ;
     RECT  20.772 33.683 36.414 33.809 ;
     RECT  37.332 33.719 38.538 33.821 ;
     RECT  37.332 33.821 38.322 33.845 ;
     RECT  37.548 33.845 38.322 33.953 ;
     RECT  2.376 33.629 20.034 33.961 ;
     RECT  2.304 33.961 20.034 33.989 ;
     RECT  20.772 33.809 36.234 33.989 ;
     RECT  2.304 33.989 19.062 34.079 ;
     RECT  19.872 33.989 20.034 34.079 ;
     RECT  32.364 33.989 36.234 34.079 ;
     RECT  2.304 34.079 18.954 34.115 ;
     RECT  37.548 33.953 38.142 34.115 ;
     RECT  6.084 34.115 18.954 34.151 ;
     RECT  20.772 33.989 31.626 34.151 ;
     RECT  32.508 34.079 36.234 34.151 ;
     RECT  20.772 34.151 30.87 34.187 ;
     RECT  32.508 34.151 32.634 34.187 ;
     RECT  33.948 34.151 36.234 34.187 ;
     RECT  38.124 34.115 38.142 34.187 ;
     RECT  34.02 34.187 36.234 34.205 ;
     RECT  20.772 34.187 25.11 34.223 ;
     RECT  34.02 34.205 35.946 34.223 ;
     RECT  6.084 34.151 18.897 34.307 ;
     RECT  22.14 34.223 24.297 34.307 ;
     RECT  34.815 34.223 35.946 34.307 ;
     RECT  40.215 33.449 40.497 34.307 ;
     RECT  2.415 34.115 5.346 34.349 ;
     RECT  6.084 34.307 18.705 34.349 ;
     RECT  20.772 34.223 20.79 34.349 ;
     RECT  22.14 34.307 24.105 34.349 ;
     RECT  26.136 34.187 30.798 34.349 ;
     RECT  32.508 34.187 32.562 34.349 ;
     RECT  35.784 34.307 35.946 34.349 ;
     RECT  3.924 34.349 4.014 34.385 ;
     RECT  4.824 34.349 4.842 34.385 ;
     RECT  6.084 34.349 6.57 34.385 ;
     RECT  7.452 34.349 11.178 34.385 ;
     RECT  11.916 34.349 18.705 34.385 ;
     RECT  26.388 34.349 30.798 34.385 ;
     RECT  35.784 34.349 35.802 34.385 ;
     RECT  13.068 34.385 18.705 34.397 ;
     RECT  26.892 34.385 30.798 34.397 ;
     RECT  3.996 34.385 4.014 34.421 ;
     RECT  7.452 34.385 10.854 34.421 ;
     RECT  11.916 34.385 11.934 34.421 ;
     RECT  14.508 34.397 18.705 34.421 ;
     RECT  26.892 34.397 29.505 34.421 ;
     RECT  13.068 34.397 13.59 34.445 ;
     RECT  6.084 34.385 6.318 34.457 ;
     RECT  16.272 34.421 18.705 34.457 ;
     RECT  16.308 34.457 18.705 34.493 ;
     RECT  22.824 34.349 24.105 34.493 ;
     RECT  28.692 34.421 29.505 34.493 ;
     RECT  31.608 34.151 31.626 34.493 ;
     RECT  32.544 34.349 32.562 34.493 ;
     RECT  6.084 34.457 6.102 34.529 ;
     RECT  14.688 34.421 15.462 34.529 ;
     RECT  26.892 34.421 27.594 34.529 ;
     RECT  30.78 34.397 30.798 34.529 ;
     RECT  7.815 34.421 10.818 34.541 ;
     RECT  2.415 34.349 2.505 34.577 ;
     RECT  7.815 34.541 7.905 34.577 ;
     RECT  16.344 34.493 18.705 34.577 ;
     RECT  23.328 34.493 24.105 34.577 ;
     RECT  29.16 34.493 29.505 34.577 ;
     RECT  34.815 34.307 34.905 34.577 ;
     RECT  40.215 34.307 40.305 34.577 ;
     RECT  13.14 34.445 13.59 34.619 ;
     RECT  14.688 34.529 14.706 34.619 ;
     RECT  16.344 34.577 17.91 34.619 ;
     RECT  23.328 34.577 23.346 34.619 ;
     RECT  29.16 34.577 29.178 34.619 ;
     RECT  16.992 34.619 17.01 34.691 ;
     RECT  17.892 34.619 17.91 34.691 ;
     RECT  8.82 34.541 10.818 34.799 ;
     RECT  8.82 34.799 10.746 34.829 ;
     RECT  8.82 34.829 9.594 35.899 ;
     RECT  10.332 34.829 10.746 35.899 ;
     RECT  8.82 35.899 11.466 36.029 ;
     RECT  13.14 34.619 13.158 36.125 ;
     RECT  9 36.029 11.466 36.588 ;
    LAYER M4 ;
     RECT  0.156 14.88 0.325 15.192 ;
     RECT  2.257 27.792 2.293 27.816 ;
     RECT  2.221 30.672 2.293 31.512 ;
     RECT  2.329 5.184 2.365 5.208 ;
     RECT  0.229 19.536 2.365 19.56 ;
     RECT  2.293 25.776 2.365 25.8 ;
     RECT  2.365 2.304 2.408 2.328 ;
     RECT  2.365 5.04 2.408 5.208 ;
     RECT  0.325 14.784 2.408 15.192 ;
     RECT  2.329 16.56 2.408 16.584 ;
     RECT  2.365 18.72 2.408 19.8 ;
     RECT  2.293 22.752 2.408 22.776 ;
     RECT  2.293 23.952 2.408 24.504 ;
     RECT  2.365 25.728 2.408 25.8 ;
     RECT  2.293 26.88 2.408 32.52 ;
     RECT  2.408 2.148 2.512 34.572 ;
     RECT  2.512 2.304 2.704 34.302 ;
     RECT  2.704 2.304 3.629 8.52 ;
     RECT  2.704 14.64 3.769 14.952 ;
     RECT  2.704 15.984 3.805 17.16 ;
     RECT  2.704 18.24 3.805 34.248 ;
     RECT  3.769 13.824 3.949 14.952 ;
     RECT  3.805 15.984 3.949 34.248 ;
     RECT  3.949 13.824 3.973 34.248 ;
     RECT  3.629 2.304 4.025 7.32 ;
     RECT  3.973 13.824 4.025 34.392 ;
     RECT  2.704 9.6 4.457 12.312 ;
     RECT  4.025 13.824 4.499 34.344 ;
     RECT  3.629 8.496 4.633 8.52 ;
     RECT  4.633 8.448 4.669 8.52 ;
     RECT  4.669 8.352 4.693 8.52 ;
     RECT  4.457 9.6 4.693 9.624 ;
     RECT  4.499 13.824 4.853 34.248 ;
     RECT  4.853 13.824 4.885 34.2 ;
     RECT  4.457 10.752 4.921 12.312 ;
     RECT  4.885 13.632 4.921 34.2 ;
     RECT  4.921 10.752 5.027 34.2 ;
     RECT  4.693 8.352 5.177 9.624 ;
     RECT  5.027 10.752 5.285 16.536 ;
     RECT  4.025 3.36 5.425 7.32 ;
     RECT  5.177 8.352 5.425 9.528 ;
     RECT  4.025 2.304 5.461 2.376 ;
     RECT  5.425 3.36 5.461 9.528 ;
     RECT  5.285 10.944 5.717 16.536 ;
     RECT  5.717 13.008 6.037 16.536 ;
     RECT  5.027 17.616 6.037 34.2 ;
     RECT  5.717 10.944 6.365 11.832 ;
     RECT  5.461 2.304 6.433 9.528 ;
     RECT  6.433 2.304 6.517 9.576 ;
     RECT  6.365 10.944 6.517 11.736 ;
     RECT  6.037 13.008 6.541 34.2 ;
     RECT  6.517 2.304 7.297 11.736 ;
     RECT  7.297 2.256 7.333 11.736 ;
     RECT  6.541 13.008 7.333 34.296 ;
     RECT  7.333 2.256 7.808 34.44 ;
     RECT  7.808 2.148 7.912 34.572 ;
     RECT  8.341 0.192 8.485 0.216 ;
     RECT  7.573 36.048 8.809 36.072 ;
     RECT  8.485 0.144 9.025 0.216 ;
     RECT  9.025 0.144 9.029 0.264 ;
     RECT  9.029 0.192 9.059 0.264 ;
     RECT  7.912 2.256 9.061 34.536 ;
     RECT  8.809 36 9.061 36.072 ;
     RECT  9.059 0.24 9.203 0.264 ;
     RECT  9.061 2.256 9.301 36.072 ;
     RECT  9.301 1.728 9.461 36.072 ;
     RECT  9.673 0.288 9.779 0.6 ;
     RECT  9.461 1.728 9.929 36.024 ;
     RECT  9.929 1.728 10.037 34.344 ;
     RECT  9.779 0.288 10.067 0.552 ;
     RECT  10.037 1.728 10.505 34.248 ;
     RECT  9.929 35.328 10.541 36.024 ;
     RECT  10.541 35.904 10.597 36.024 ;
     RECT  10.505 1.824 10.643 34.248 ;
     RECT  10.643 2.256 10.865 34.248 ;
     RECT  10.067 0.288 11.029 0.504 ;
     RECT  11.029 0.192 11.077 0.504 ;
     RECT  10.597 35.904 11.173 36.072 ;
     RECT  10.865 17.328 11.293 34.248 ;
     RECT  11.173 35.904 11.507 36.12 ;
     RECT  11.507 36 11.699 36.12 ;
     RECT  11.293 17.328 11.893 34.296 ;
     RECT  10.865 2.256 12.013 16.296 ;
     RECT  12.013 1.728 12.265 16.296 ;
     RECT  11.893 17.328 12.265 34.392 ;
     RECT  12.265 1.728 13.057 34.392 ;
     RECT  11.699 36.096 13.169 36.12 ;
     RECT  13.057 1.728 13.208 34.44 ;
     RECT  13.208 1.728 13.312 34.572 ;
     RECT  13.312 1.728 13.504 34.488 ;
     RECT  11.077 0.192 13.667 0.552 ;
     RECT  13.504 24.96 13.667 34.488 ;
     RECT  13.504 1.728 13.673 23.784 ;
     RECT  13.667 24.96 13.709 34.44 ;
     RECT  13.673 2.064 13.715 23.784 ;
     RECT  13.667 0.192 13.763 0.216 ;
     RECT  13.715 2.16 13.817 23.784 ;
     RECT  13.817 2.16 13.853 16.68 ;
     RECT  13.853 2.16 14.147 16.632 ;
     RECT  13.817 18.528 14.677 23.784 ;
     RECT  13.709 25.056 14.677 34.44 ;
     RECT  14.677 18.528 14.681 34.44 ;
     RECT  14.147 2.208 14.789 16.632 ;
     RECT  14.681 19.296 15.257 34.44 ;
     RECT  15.257 19.296 15.545 34.392 ;
     RECT  15.545 19.296 15.757 34.248 ;
     RECT  14.789 2.208 16.009 16.584 ;
     RECT  16.009 2.208 16.021 16.968 ;
     RECT  15.757 18.768 16.049 34.248 ;
     RECT  16.049 19.344 16.513 34.248 ;
     RECT  16.513 19.344 16.517 34.344 ;
     RECT  16.021 2.208 16.553 17.64 ;
     RECT  16.553 14.496 16.589 17.64 ;
     RECT  16.553 2.208 16.697 13.08 ;
     RECT  16.517 19.344 16.835 26.184 ;
     RECT  16.517 27.216 16.979 34.344 ;
     RECT  16.697 2.736 17.273 13.08 ;
     RECT  16.979 27.936 17.417 34.344 ;
     RECT  16.589 14.64 17.489 17.64 ;
     RECT  17.489 17.472 17.521 17.64 ;
     RECT  16.835 19.344 17.521 25.752 ;
     RECT  17.521 17.472 17.603 25.752 ;
     RECT  17.273 13.056 17.629 13.08 ;
     RECT  17.489 14.64 17.629 16.44 ;
     RECT  17.603 24.192 17.881 25.752 ;
     RECT  17.557 26.784 17.881 26.808 ;
     RECT  17.273 2.736 18.061 12.072 ;
     RECT  17.881 24.192 18.133 26.808 ;
     RECT  17.417 27.936 18.133 33.72 ;
     RECT  17.603 17.472 18.565 17.784 ;
     RECT  17.603 19.296 18.565 23.208 ;
     RECT  18.061 2.592 18.601 12.072 ;
     RECT  17.629 13.056 18.601 16.44 ;
     RECT  18.601 2.592 18.608 16.44 ;
     RECT  18.565 17.472 18.608 23.208 ;
     RECT  18.133 24.192 18.608 33.72 ;
     RECT  18.608 2.148 18.712 34.572 ;
     RECT  18.712 2.256 18.904 34.302 ;
     RECT  18.904 2.256 19.043 33.624 ;
     RECT  19.043 2.256 19.073 26.28 ;
     RECT  19.073 2.256 19.145 25.56 ;
     RECT  19.043 27.6 19.181 33.624 ;
     RECT  19.181 28.464 19.187 33.624 ;
     RECT  19.145 6.24 19.331 25.56 ;
     RECT  19.331 6.24 19.541 17.64 ;
     RECT  19.331 18.672 19.859 25.128 ;
     RECT  19.145 2.256 19.937 5.256 ;
     RECT  19.859 18.672 20.081 19.56 ;
     RECT  19.937 2.544 20.293 5.256 ;
     RECT  19.541 6.24 20.293 7.176 ;
     RECT  20.221 26.928 20.293 26.952 ;
     RECT  19.859 20.544 20.339 25.128 ;
     RECT  20.339 21.936 20.387 25.128 ;
     RECT  19.187 28.512 20.401 33.624 ;
     RECT  20.401 28.32 20.437 33.624 ;
     RECT  20.387 22.176 20.545 25.128 ;
     RECT  20.545 22.176 20.627 25.752 ;
     RECT  20.293 2.544 20.837 7.176 ;
     RECT  20.627 23.328 20.837 24.552 ;
     RECT  20.081 18.768 20.869 19.56 ;
     RECT  20.339 20.544 20.869 20.76 ;
     RECT  20.627 25.728 21.125 25.752 ;
     RECT  20.293 26.928 21.157 27.336 ;
     RECT  20.437 28.32 21.157 34.248 ;
     RECT  20.869 18.768 21.485 20.76 ;
     RECT  20.837 2.592 21.517 7.176 ;
     RECT  19.541 8.208 21.517 17.64 ;
     RECT  21.517 2.592 21.587 17.64 ;
     RECT  20.627 22.176 21.637 22.344 ;
     RECT  20.837 23.328 21.637 23.88 ;
     RECT  21.157 26.736 21.637 34.248 ;
     RECT  21.637 22.176 21.683 23.88 ;
     RECT  21.637 26.736 21.701 34.392 ;
     RECT  21.701 30.048 21.845 34.392 ;
     RECT  21.701 26.736 21.881 29.064 ;
     RECT  21.485 20.496 21.949 20.76 ;
     RECT  21.845 30.144 22.313 34.392 ;
     RECT  21.485 18.768 22.489 19.512 ;
     RECT  21.949 20.496 22.489 21.192 ;
     RECT  22.489 18.768 22.547 21.192 ;
     RECT  22.547 20.688 22.693 21.192 ;
     RECT  21.683 22.224 22.693 23.88 ;
     RECT  22.693 20.688 22.781 23.88 ;
     RECT  21.587 2.592 22.813 7.176 ;
     RECT  21.587 8.208 22.813 17.64 ;
     RECT  22.313 33.264 22.813 34.392 ;
     RECT  22.813 2.592 22.817 17.64 ;
     RECT  22.453 26.208 22.853 26.232 ;
     RECT  22.547 18.768 22.889 19.608 ;
     RECT  22.781 20.688 22.961 21.192 ;
     RECT  21.881 27.792 23.065 29.064 ;
     RECT  22.313 30.144 23.065 32.184 ;
     RECT  23.029 26.592 23.125 26.616 ;
     RECT  23.065 27.792 23.125 32.184 ;
     RECT  22.781 22.224 23.533 23.88 ;
     RECT  22.165 25.056 23.533 25.08 ;
     RECT  22.817 2.832 24.008 17.64 ;
     RECT  22.889 18.768 24.008 19.605 ;
     RECT  22.961 20.688 24.008 21.144 ;
     RECT  23.533 22.224 24.008 25.08 ;
     RECT  23.125 26.592 24.008 32.184 ;
     RECT  22.813 33.264 24.008 34.488 ;
     RECT  24.008 2.148 24.112 34.572 ;
     RECT  24.112 2.256 24.304 34.488 ;
     RECT  24.304 2.256 24.419 16.392 ;
     RECT  24.304 19.488 24.419 21.192 ;
     RECT  24.304 22.32 24.419 24.408 ;
     RECT  24.419 2.256 24.437 16.344 ;
     RECT  24.304 27.792 24.509 27.96 ;
     RECT  24.437 2.256 24.689 13.032 ;
     RECT  24.419 19.488 25.085 20.04 ;
     RECT  24.419 22.704 25.121 24.408 ;
     RECT  25.121 23.376 25.193 24.408 ;
     RECT  25.085 19.488 25.285 19.656 ;
     RECT  25.285 18.72 25.331 19.656 ;
     RECT  25.331 18.72 25.337 19.509 ;
     RECT  24.689 2.736 25.379 13.032 ;
     RECT  24.509 27.792 25.549 27.816 ;
     RECT  24.304 26.112 25.573 26.664 ;
     RECT  25.193 23.376 25.619 24.312 ;
     RECT  25.549 27.792 25.733 27.864 ;
     RECT  25.621 17.616 25.841 17.64 ;
     RECT  24.419 21.12 25.873 21.192 ;
     RECT  25.573 25.68 25.873 26.664 ;
     RECT  25.873 21.12 25.877 21.672 ;
     RECT  25.733 27.84 25.945 27.864 ;
     RECT  24.304 28.944 25.945 34.488 ;
     RECT  25.379 2.736 25.949 8.52 ;
     RECT  25.873 25.68 26.089 26.76 ;
     RECT  25.619 23.376 26.345 23.88 ;
     RECT  24.437 14.208 26.665 16.344 ;
     RECT  26.345 23.856 26.737 23.88 ;
     RECT  26.089 25.488 26.737 26.76 ;
     RECT  25.949 2.832 26.773 8.52 ;
     RECT  25.379 9.696 26.773 13.032 ;
     RECT  26.665 14.208 26.777 17.112 ;
     RECT  26.777 14.208 26.813 15.192 ;
     RECT  26.777 16.32 26.819 17.112 ;
     RECT  26.819 16.32 26.849 16.536 ;
     RECT  26.849 16.32 26.885 16.344 ;
     RECT  26.773 2.832 27.061 13.032 ;
     RECT  26.813 14.208 27.061 15.096 ;
     RECT  27.061 2.832 27.155 15.096 ;
     RECT  26.737 23.856 27.253 26.76 ;
     RECT  25.945 27.84 27.253 34.488 ;
     RECT  27.155 8.16 27.317 15.096 ;
     RECT  27.317 10.128 27.347 15.096 ;
     RECT  27.253 23.856 27.497 34.488 ;
     RECT  27.497 26.16 27.533 34.488 ;
     RECT  25.877 21.648 27.605 21.672 ;
     RECT  27.155 2.832 27.731 6.936 ;
     RECT  27.529 18.144 27.853 18.168 ;
     RECT  25.337 19.491 27.853 19.509 ;
     RECT  27.317 8.16 27.929 9 ;
     RECT  27.731 2.832 28.165 3.432 ;
     RECT  28.165 2.592 28.181 3.432 ;
     RECT  27.997 22.848 28.253 22.872 ;
     RECT  27.497 24.48 28.253 25.128 ;
     RECT  27.929 8.4 28.289 9 ;
     RECT  27.533 26.16 28.361 34.392 ;
     RECT  27.731 4.752 28.741 6.936 ;
     RECT  27.853 18.144 28.741 19.509 ;
     RECT  28.289 8.496 28.789 9 ;
     RECT  27.347 10.128 28.789 13.032 ;
     RECT  28.361 26.16 28.861 27.72 ;
     RECT  28.789 8.496 29.041 13.032 ;
     RECT  28.741 18.144 29.041 19.944 ;
     RECT  28.861 26.112 29.041 27.72 ;
     RECT  28.253 24.48 29.149 24.648 ;
     RECT  29.041 18.144 29.185 20.088 ;
     RECT  29.149 23.664 29.221 24.648 ;
     RECT  29.041 25.728 29.221 27.72 ;
     RECT  29.041 17.088 29.257 17.112 ;
     RECT  29.185 18.144 29.257 20.424 ;
     RECT  28.741 4.512 29.269 6.936 ;
     RECT  29.041 8.496 29.269 13.128 ;
     RECT  27.347 14.352 29.269 15.096 ;
     RECT  28.969 22.032 29.365 22.056 ;
     RECT  29.221 23.664 29.365 27.72 ;
     RECT  28.181 2.592 29.408 3.336 ;
     RECT  29.269 4.512 29.408 15.096 ;
     RECT  29.257 17.088 29.408 20.424 ;
     RECT  29.365 22.032 29.408 27.72 ;
     RECT  28.361 28.848 29.408 34.392 ;
     RECT  29.408 2.148 29.512 34.572 ;
     RECT  29.512 2.418 29.704 34.392 ;
     RECT  29.704 31.776 29.729 34.392 ;
     RECT  29.704 16.8 29.765 19.56 ;
     RECT  29.729 31.92 29.765 34.392 ;
     RECT  29.704 2.592 29.873 8.52 ;
     RECT  29.765 16.8 29.909 19.32 ;
     RECT  29.704 20.592 29.909 27.72 ;
     RECT  29.704 28.944 29.939 30.216 ;
     RECT  29.873 2.64 30.035 5.592 ;
     RECT  29.909 22.032 30.089 27.72 ;
     RECT  29.909 20.592 30.125 20.904 ;
     RECT  29.909 16.8 30.161 18.168 ;
     RECT  29.765 31.968 30.161 34.392 ;
     RECT  30.089 22.992 30.227 27.72 ;
     RECT  30.035 4.176 30.341 5.592 ;
     RECT  30.227 22.992 30.377 24.12 ;
     RECT  30.035 2.64 30.413 2.952 ;
     RECT  30.341 4.512 30.449 5.592 ;
     RECT  30.161 31.968 30.485 34.2 ;
     RECT  29.704 9.648 30.557 15.576 ;
     RECT  29.873 6.768 30.593 8.52 ;
     RECT  29.909 19.296 30.733 19.32 ;
     RECT  30.485 31.968 30.733 34.152 ;
     RECT  30.161 16.8 30.769 17.544 ;
     RECT  29.939 28.944 30.805 30.12 ;
     RECT  30.449 4.704 30.877 5.592 ;
     RECT  30.593 6.768 30.877 7.992 ;
     RECT  30.769 16.752 30.877 17.544 ;
     RECT  30.557 10.176 30.881 15.576 ;
     RECT  30.413 2.64 30.917 2.904 ;
     RECT  30.877 4.704 30.989 7.992 ;
     RECT  30.733 31.44 31.057 34.152 ;
     RECT  30.733 19.296 31.093 19.368 ;
     RECT  30.805 28.8 31.241 30.12 ;
     RECT  30.377 23.568 31.273 24.12 ;
     RECT  30.227 25.392 31.273 27.72 ;
     RECT  31.057 31.2 31.273 34.152 ;
     RECT  31.273 23.568 31.381 27.72 ;
     RECT  31.241 28.8 31.421 29.832 ;
     RECT  31.381 23.568 31.453 27.816 ;
     RECT  31.421 28.8 31.453 29.784 ;
     RECT  31.093 19.056 31.489 19.368 ;
     RECT  30.917 2.784 31.561 2.904 ;
     RECT  31.525 21.84 31.561 21.864 ;
     RECT  31.561 2.784 31.565 3.048 ;
     RECT  30.769 9.12 31.601 9.192 ;
     RECT  31.489 19.008 31.741 19.368 ;
     RECT  31.273 31.104 31.781 34.152 ;
     RECT  30.125 20.592 31.813 20.712 ;
     RECT  31.741 18.96 31.849 19.368 ;
     RECT  31.813 20.448 31.849 20.712 ;
     RECT  31.453 23.568 31.849 29.784 ;
     RECT  30.989 4.704 31.925 6.168 ;
     RECT  30.881 10.176 31.961 15.048 ;
     RECT  31.925 5.808 31.997 6.168 ;
     RECT  30.989 7.344 31.997 7.752 ;
     RECT  31.849 18.96 32.141 20.712 ;
     RECT  31.997 7.392 32.173 7.752 ;
     RECT  31.961 13.392 32.317 15.048 ;
     RECT  30.877 16.656 32.317 17.544 ;
     RECT  31.561 21.84 32.317 22.248 ;
     RECT  31.849 23.328 32.317 29.784 ;
     RECT  31.601 9.168 32.425 9.192 ;
     RECT  31.961 10.176 32.425 11.976 ;
     RECT  31.925 4.704 32.537 4.776 ;
     RECT  32.317 21.84 32.569 29.784 ;
     RECT  32.317 13.392 32.573 17.544 ;
     RECT  32.141 20.448 32.573 20.712 ;
     RECT  32.569 21.84 32.627 29.976 ;
     RECT  32.627 21.84 32.641 27.96 ;
     RECT  31.565 2.832 32.677 3.048 ;
     RECT  32.141 18.96 32.713 19.32 ;
     RECT  32.425 9.168 32.725 11.976 ;
     RECT  32.677 2.832 32.749 3.432 ;
     RECT  32.713 18.576 32.771 19.32 ;
     RECT  32.641 21.12 32.771 27.96 ;
     RECT  32.725 9.072 32.789 11.976 ;
     RECT  32.789 9.792 32.861 11.976 ;
     RECT  32.749 2.784 33.013 3.432 ;
     RECT  32.573 13.392 33.041 14.376 ;
     RECT  32.573 15.792 33.041 17.544 ;
     RECT  31.781 31.2 33.041 34.152 ;
     RECT  32.173 7.392 33.109 7.992 ;
     RECT  32.771 18.672 33.217 19.32 ;
     RECT  33.041 31.344 33.293 34.152 ;
     RECT  33.109 7.392 33.299 8.76 ;
     RECT  33.217 18.672 33.365 19.368 ;
     RECT  32.771 22.08 33.365 27.96 ;
     RECT  33.365 22.08 33.509 24.696 ;
     RECT  33.293 31.344 33.509 32.472 ;
     RECT  33.299 7.968 33.635 8.76 ;
     RECT  33.635 7.968 33.653 8.52 ;
     RECT  33.365 26.112 33.685 27.96 ;
     RECT  33.041 15.792 33.689 17.448 ;
     RECT  33.509 31.44 33.689 32.472 ;
     RECT  33.689 15.792 33.793 16.968 ;
     RECT  33.653 8.4 33.797 8.52 ;
     RECT  32.861 9.888 33.829 11.976 ;
     RECT  33.829 9.504 34.045 11.976 ;
     RECT  33.041 13.392 34.045 13.416 ;
     RECT  33.013 2.784 34.153 3.72 ;
     RECT  32.537 4.752 34.153 4.776 ;
     RECT  31.997 5.808 34.153 5.88 ;
     RECT  33.689 31.92 34.261 32.472 ;
     RECT  33.293 33.648 34.261 34.152 ;
     RECT  33.685 26.112 34.369 28.44 ;
     RECT  33.509 24.672 34.441 24.696 ;
     RECT  34.441 24.672 34.585 24.984 ;
     RECT  33.509 22.08 34.693 23.352 ;
     RECT  34.585 24.48 34.693 24.984 ;
     RECT  34.369 26.112 34.693 28.488 ;
     RECT  32.627 29.76 34.693 29.784 ;
     RECT  34.045 9.504 34.765 13.416 ;
     RECT  33.365 18.768 34.765 19.368 ;
     RECT  34.153 2.784 34.808 5.88 ;
     RECT  34.441 7.392 34.808 7.416 ;
     RECT  33.797 8.496 34.808 8.52 ;
     RECT  34.765 9.504 34.808 13.608 ;
     RECT  33.793 14.88 34.808 16.968 ;
     RECT  34.765 18.24 34.808 19.368 ;
     RECT  34.693 22.08 34.808 24.984 ;
     RECT  34.693 26.112 34.808 29.784 ;
     RECT  34.261 31.92 34.808 34.152 ;
     RECT  34.808 2.148 34.912 34.572 ;
     RECT  34.912 2.208 35.104 34.302 ;
     RECT  35.104 9.504 35.165 13.608 ;
     RECT  35.104 2.208 35.345 7.416 ;
     RECT  35.104 8.4 35.525 8.52 ;
     RECT  35.104 31.968 35.885 34.2 ;
     RECT  35.104 22.752 36.097 26.136 ;
     RECT  35.104 15.744 36.101 16.92 ;
     RECT  35.104 18.72 36.101 21.528 ;
     RECT  36.101 16.56 36.169 16.92 ;
     RECT  35.345 2.208 36.245 7.368 ;
     RECT  35.885 33.792 36.245 34.2 ;
     RECT  36.169 16.56 36.313 17.16 ;
     RECT  36.101 21.264 36.313 21.528 ;
     RECT  36.097 22.704 36.313 26.136 ;
     RECT  36.245 2.208 36.353 4.68 ;
     RECT  36.101 18.72 36.353 19.704 ;
     RECT  35.165 12.768 36.385 13.608 ;
     RECT  35.165 9.504 36.389 11.688 ;
     RECT  36.133 30.912 36.389 30.936 ;
     RECT  36.313 21.264 36.419 26.136 ;
     RECT  35.104 27.648 36.467 29.784 ;
     RECT  35.885 31.968 36.497 32.568 ;
     RECT  36.245 6.528 36.565 7.368 ;
     RECT  35.525 8.4 36.565 8.472 ;
     RECT  36.385 12.768 36.569 13.656 ;
     RECT  36.467 27.648 36.677 29.592 ;
     RECT  36.677 27.648 36.709 29.4 ;
     RECT  36.601 14.784 36.713 14.808 ;
     RECT  36.569 12.768 36.749 13.416 ;
     RECT  36.497 31.968 36.749 32.376 ;
     RECT  36.353 2.832 36.785 4.68 ;
     RECT  36.709 27.312 36.785 29.4 ;
     RECT  36.785 4.656 36.821 4.68 ;
     RECT  36.785 27.312 37.073 28.968 ;
     RECT  36.565 6.528 37.105 8.472 ;
     RECT  36.389 9.504 37.105 9.672 ;
     RECT  37.105 6.528 37.109 9.672 ;
     RECT  36.749 31.968 37.109 32.28 ;
     RECT  36.389 10.848 37.217 11.688 ;
     RECT  37.109 6.528 37.249 6.84 ;
     RECT  36.313 16.56 37.249 17.208 ;
     RECT  37.249 16.56 37.289 17.688 ;
     RECT  36.785 2.832 37.429 3.432 ;
     RECT  36.419 22.176 37.429 26.136 ;
     RECT  37.073 27.312 37.433 27.336 ;
     RECT  37.217 10.848 37.505 11.304 ;
     RECT  36.353 18.72 37.537 19.272 ;
     RECT  37.537 18.672 37.649 19.272 ;
     RECT  37.073 28.848 37.649 28.968 ;
     RECT  36.749 12.768 37.685 13.128 ;
     RECT  37.109 31.968 37.685 32.232 ;
     RECT  37.109 7.92 37.721 9.672 ;
     RECT  37.649 18.72 37.793 19.272 ;
     RECT  37.721 7.92 37.907 9.528 ;
     RECT  37.249 6.336 37.937 6.84 ;
     RECT  37.649 28.944 37.973 28.968 ;
     RECT  37.429 22.176 38.003 26.232 ;
     RECT  38.003 25.104 38.041 26.232 ;
     RECT  38.003 22.176 38.077 24.12 ;
     RECT  37.289 16.848 38.117 17.688 ;
     RECT  37.793 18.96 38.189 19.272 ;
     RECT  37.907 7.92 38.261 8.856 ;
     RECT  38.041 25.104 38.261 26.952 ;
     RECT  37.685 12.768 38.297 12.792 ;
     RECT  38.077 21.552 38.297 24.12 ;
     RECT  37.897 5.328 38.329 5.352 ;
     RECT  36.245 33.792 38.333 33.912 ;
     RECT  37.573 30.816 38.405 30.84 ;
     RECT  37.505 10.944 38.473 11.304 ;
     RECT  38.437 30.48 38.473 30.504 ;
     RECT  38.333 33.792 38.473 33.816 ;
     RECT  38.257 16.656 38.513 16.68 ;
     RECT  37.429 2.736 38.533 3.432 ;
     RECT  38.329 5.04 38.533 5.352 ;
     RECT  38.473 33.264 38.549 33.816 ;
     RECT  38.297 21.552 38.585 24.072 ;
     RECT  37.685 32.064 38.689 32.232 ;
     RECT  38.197 20.496 38.725 20.52 ;
     RECT  38.585 21.552 38.725 22.824 ;
     RECT  38.473 30.192 38.765 30.504 ;
     RECT  38.261 8.832 38.801 8.856 ;
     RECT  38.005 14.16 38.801 14.184 ;
     RECT  38.765 30.48 38.801 30.504 ;
     RECT  37.537 15.168 38.837 15.192 ;
     RECT  38.261 25.296 38.981 26.952 ;
     RECT  38.689 31.968 38.981 32.232 ;
     RECT  38.533 2.736 39.049 5.352 ;
     RECT  37.937 6.336 39.049 6.552 ;
     RECT  38.549 33.264 39.053 33.288 ;
     RECT  39.049 2.736 39.193 6.552 ;
     RECT  38.981 31.968 39.445 32.136 ;
     RECT  38.981 25.296 39.553 26.232 ;
     RECT  38.473 10.848 39.733 12.552 ;
     RECT  39.337 13.968 39.769 13.992 ;
     RECT  39.193 2.256 39.913 6.552 ;
     RECT  39.409 9.504 39.925 9.528 ;
     RECT  39.733 10.8 40.069 12.552 ;
     RECT  39.769 13.968 40.069 14.28 ;
     RECT  39.913 2.256 40.208 6.84 ;
     RECT  39.925 7.824 40.208 7.848 ;
     RECT  39.925 8.928 40.208 9.528 ;
     RECT  40.069 10.8 40.208 14.28 ;
     RECT  38.117 17.664 40.208 17.688 ;
     RECT  38.189 18.96 40.208 18.984 ;
     RECT  38.725 20.496 40.208 22.824 ;
     RECT  38.585 23.904 40.208 24.072 ;
     RECT  39.553 25.056 40.208 26.232 ;
     RECT  39.445 31.632 40.208 32.136 ;
     RECT  40.208 2.148 40.312 34.572 ;
     RECT  40.312 2.418 40.504 34.302 ;
     RECT  40.504 11.232 40.709 11.256 ;
    LAYER M5 ;
     RECT  8.496 0.133 8.52 0.144 ;
     RECT  8.496 0.144 13.512 0.181 ;
     RECT  8.496 0.181 13.752 2.137 ;
     RECT  7.8 2.137 13.752 2.149 ;
     RECT  2.4 2.137 2.52 2.151 ;
     RECT  18.6 2.137 18.72 2.151 ;
     RECT  24 2.137 24.12 2.151 ;
     RECT  29.4 2.137 29.52 2.151 ;
     RECT  34.8 2.137 34.92 2.151 ;
     RECT  40.2 2.137 40.32 2.151 ;
     RECT  7.8 2.149 14.136 2.245 ;
     RECT  18.6 2.151 18.912 2.245 ;
     RECT  24 2.151 24.312 2.245 ;
     RECT  7.344 2.245 14.184 2.341 ;
     RECT  6.432 2.341 14.184 2.485 ;
     RECT  15.36 2.197 15.384 2.485 ;
     RECT  18.6 2.245 19.704 2.581 ;
     RECT  6.432 2.485 15.384 2.629 ;
     RECT  40.2 2.151 40.512 2.725 ;
     RECT  18.6 2.581 19.992 2.773 ;
     RECT  18.6 2.773 20.376 2.821 ;
     RECT  34.8 2.151 35.112 2.869 ;
     RECT  29.4 2.151 29.712 2.917 ;
     RECT  28.176 2.581 28.2 2.963 ;
     RECT  2.4 2.151 2.712 3.061 ;
     RECT  34.704 2.869 35.112 3.061 ;
     RECT  18.6 2.821 21.144 3.301 ;
     RECT  26.736 2.821 26.76 3.301 ;
     RECT  26.736 3.301 28.152 3.397 ;
     RECT  33.024 3.349 33.048 3.397 ;
     RECT  39.552 2.725 40.512 3.397 ;
     RECT  24 2.245 24.648 3.443 ;
     RECT  18.6 3.301 21.912 3.637 ;
     RECT  6.432 2.629 16.152 3.685 ;
     RECT  5.616 3.685 16.152 3.877 ;
     RECT  26.688 3.397 28.152 4.115 ;
     RECT  18.432 3.637 21.912 4.117 ;
     RECT  18.432 4.117 22.2 4.163 ;
     RECT  29.4 2.917 30.024 4.165 ;
     RECT  39.312 3.397 40.512 4.261 ;
     RECT  33.024 3.397 33.624 4.453 ;
     RECT  34.704 3.061 35.352 4.453 ;
     RECT  5.616 3.877 17.064 4.501 ;
     RECT  24 3.443 24.312 4.501 ;
     RECT  26.736 4.115 28.152 4.501 ;
     RECT  29.4 4.165 30.312 4.501 ;
     RECT  33.024 4.453 35.352 4.501 ;
     RECT  18.432 4.163 21.144 4.547 ;
     RECT  4.896 4.501 17.064 4.933 ;
     RECT  4.896 4.933 17.112 5.029 ;
     RECT  38.544 4.261 40.512 5.363 ;
     RECT  20.256 4.547 21.144 5.459 ;
     RECT  23.664 4.501 24.312 5.509 ;
     RECT  2.4 3.061 3.48 5.605 ;
     RECT  4.896 5.029 17.16 5.605 ;
     RECT  25.68 4.453 25.704 5.605 ;
     RECT  26.736 4.501 30.312 5.605 ;
     RECT  25.68 5.605 30.312 5.651 ;
     RECT  33.024 4.501 35.4 5.699 ;
     RECT  26.208 5.651 30.312 5.747 ;
     RECT  39.312 5.363 40.512 5.747 ;
     RECT  28.128 5.747 30.312 5.795 ;
     RECT  33.024 5.699 33.624 5.891 ;
     RECT  18.432 4.547 18.912 6.035 ;
     RECT  22.176 4.163 22.2 6.035 ;
     RECT  23.664 5.509 24.408 6.325 ;
     RECT  18.6 6.035 18.912 6.565 ;
     RECT  20.256 5.459 20.376 6.565 ;
     RECT  28.128 5.795 28.152 6.659 ;
     RECT  40.2 5.747 40.512 6.709 ;
     RECT  29.4 5.795 30.312 6.757 ;
     RECT  34.8 5.699 35.4 6.805 ;
     RECT  23.664 6.325 25.128 6.853 ;
     RECT  26.208 5.747 26.472 6.853 ;
     RECT  2.4 5.605 17.16 6.899 ;
     RECT  29.4 6.757 30.936 6.901 ;
     RECT  2.4 6.899 16.392 6.947 ;
     RECT  34.8 6.805 35.448 7.091 ;
     RECT  18.6 6.565 20.376 7.187 ;
     RECT  18.6 7.187 19.752 7.189 ;
     RECT  23.664 6.853 26.472 7.237 ;
     RECT  33.6 5.891 33.624 7.381 ;
     RECT  23.664 7.237 27.144 7.475 ;
     RECT  25.344 7.475 27.144 7.667 ;
     RECT  3.696 6.947 16.392 7.859 ;
     RECT  23.664 7.475 24.312 7.907 ;
     RECT  29.28 6.901 30.936 7.907 ;
     RECT  29.4 7.907 30.936 8.003 ;
     RECT  2.4 6.947 2.712 8.437 ;
     RECT  3.696 7.859 16.248 8.437 ;
     RECT  17.808 7.189 19.752 8.437 ;
     RECT  25.344 7.667 25.368 8.771 ;
     RECT  33.264 7.381 33.624 8.771 ;
     RECT  21.552 6.805 21.576 9.061 ;
     RECT  23.808 7.907 24.312 9.061 ;
     RECT  33.264 8.771 33.288 9.061 ;
     RECT  21.552 9.061 22.2 9.155 ;
     RECT  26.448 7.667 27.144 9.251 ;
     RECT  2.4 8.437 16.248 9.299 ;
     RECT  17.664 8.437 19.752 9.299 ;
     RECT  37.872 8.821 37.896 9.539 ;
     RECT  39.936 6.709 40.512 9.539 ;
     RECT  2.4 9.299 15.864 9.635 ;
     RECT  5.616 9.635 15.864 9.683 ;
     RECT  23.808 9.061 24.648 9.731 ;
     RECT  17.664 9.299 18.912 9.779 ;
     RECT  24 9.731 24.648 9.779 ;
     RECT  34.8 7.091 35.4 10.165 ;
     RECT  32.736 9.061 33.288 10.211 ;
     RECT  22.176 9.155 22.2 10.213 ;
     RECT  30.816 8.003 30.84 10.307 ;
     RECT  33.264 10.211 33.288 10.355 ;
     RECT  29.4 8.003 29.712 10.453 ;
     RECT  29.4 10.453 29.832 10.597 ;
     RECT  28.752 10.597 29.832 10.643 ;
     RECT  26.448 9.251 26.808 10.645 ;
     RECT  5.616 9.683 15.768 10.741 ;
     RECT  24 9.779 24.312 10.741 ;
     RECT  2.4 9.635 4.104 10.789 ;
     RECT  34.8 10.165 35.64 10.883 ;
     RECT  2.4 10.789 4.584 10.931 ;
     RECT  26.448 10.645 27.192 10.933 ;
     RECT  18.48 9.779 18.912 10.981 ;
     RECT  25.92 10.933 27.192 11.029 ;
     RECT  28.755 10.643 29.832 11.125 ;
     RECT  40.2 9.539 40.512 11.221 ;
     RECT  5.616 10.741 16.2 11.317 ;
     RECT  5.616 11.317 16.584 11.365 ;
     RECT  17.616 10.981 18.912 11.365 ;
     RECT  5.616 11.365 18.912 11.459 ;
     RECT  28.755 11.125 30.12 11.507 ;
     RECT  5.616 11.459 17.304 11.651 ;
     RECT  34.8 10.883 35.4 11.699 ;
     RECT  24 10.741 24.936 11.747 ;
     RECT  3.888 10.931 4.584 11.797 ;
     RECT  40.08 11.221 40.512 11.941 ;
     RECT  21.456 10.213 22.2 12.229 ;
     RECT  21.456 12.229 22.344 12.613 ;
     RECT  6.576 11.651 17.304 12.995 ;
     RECT  20.496 12.613 22.344 13.045 ;
     RECT  19.968 13.045 22.344 13.139 ;
     RECT  37.344 11.029 37.368 13.139 ;
     RECT  6.576 12.995 15.672 13.187 ;
     RECT  3.888 11.797 5.496 13.333 ;
     RECT  6.576 13.187 14.616 13.333 ;
     RECT  18.48 11.459 18.912 13.525 ;
     RECT  19.968 13.139 21.528 13.525 ;
     RECT  18.48 13.525 21.528 13.571 ;
     RECT  25.92 11.029 27.336 13.715 ;
     RECT  39.36 11.941 40.512 14.003 ;
     RECT  3.888 13.333 14.616 14.243 ;
     RECT  18.48 13.571 21.48 14.387 ;
     RECT  25.92 13.715 27.048 14.483 ;
     RECT  20.16 14.387 21.48 14.627 ;
     RECT  2.4 10.931 2.712 14.629 ;
     RECT  3.888 14.243 6.12 14.629 ;
     RECT  15.648 13.187 15.672 14.725 ;
     RECT  18.48 14.387 18.912 14.773 ;
     RECT  0.336 14.773 0.36 14.869 ;
     RECT  0.24 14.869 0.36 15.059 ;
     RECT  22.704 14.197 22.728 15.107 ;
     RECT  7.104 14.243 14.616 15.445 ;
     RECT  15.648 14.725 16.008 15.445 ;
     RECT  20.16 14.627 21.336 15.491 ;
     RECT  20.16 15.491 21.144 15.635 ;
     RECT  20.544 15.635 21.144 15.731 ;
     RECT  18.432 14.773 18.912 15.781 ;
     RECT  18.432 15.781 19.32 15.829 ;
     RECT  21.12 15.731 21.144 16.019 ;
     RECT  24 11.747 24.648 16.019 ;
     RECT  25.92 14.483 26.76 16.019 ;
     RECT  17.28 12.995 17.304 16.069 ;
     RECT  18.384 15.829 19.32 16.069 ;
     RECT  26.496 16.019 26.76 16.259 ;
     RECT  7.104 15.445 16.008 16.933 ;
     RECT  7.104 16.933 16.056 16.981 ;
     RECT  17.28 16.069 19.32 16.981 ;
     RECT  22.704 16.309 22.728 17.029 ;
     RECT  2.4 14.629 6.12 17.077 ;
     RECT  7.104 16.981 19.32 17.077 ;
     RECT  26.784 16.501 26.808 17.123 ;
     RECT  37.008 17.077 37.032 17.219 ;
     RECT  22.704 17.029 22.776 17.605 ;
     RECT  24 16.019 24.408 17.605 ;
     RECT  2.4 17.077 19.32 17.651 ;
     RECT  16.992 17.651 19.32 18.709 ;
     RECT  22.704 17.605 24.408 18.709 ;
     RECT  2.4 17.651 15.816 19.333 ;
     RECT  28.755 11.507 29.712 19.477 ;
     RECT  0.24 15.059 0.264 19.571 ;
     RECT  22.704 18.709 25.32 19.667 ;
     RECT  28.752 19.477 29.712 19.955 ;
     RECT  22.704 19.667 24.408 20.341 ;
     RECT  16.992 18.709 19.368 20.485 ;
     RECT  16.992 20.485 19.848 20.533 ;
     RECT  22.512 20.341 24.408 20.723 ;
     RECT  2.4 19.333 15.96 20.725 ;
     RECT  16.992 20.533 20.376 20.725 ;
     RECT  22.512 20.723 24.312 20.725 ;
     RECT  2.4 20.725 20.376 21.155 ;
     RECT  32.736 18.565 32.76 21.155 ;
     RECT  2.4 21.155 17.016 21.251 ;
     RECT  38.208 20.485 38.232 21.397 ;
     RECT  40.2 14.003 40.512 21.397 ;
     RECT  36.384 21.253 36.408 22.117 ;
     RECT  38.208 21.397 38.76 22.117 ;
     RECT  39.744 21.397 40.512 22.117 ;
     RECT  36.336 22.117 36.408 22.165 ;
     RECT  2.4 21.251 16.68 22.211 ;
     RECT  2.4 22.211 16.104 22.259 ;
     RECT  38.208 22.117 40.512 22.259 ;
     RECT  18 21.155 20.376 22.261 ;
     RECT  21.6 20.725 24.312 22.261 ;
     RECT  38.736 22.259 40.512 22.307 ;
     RECT  18 22.261 24.312 22.309 ;
     RECT  18 22.309 24.408 22.355 ;
     RECT  32.736 22.165 32.76 22.693 ;
     RECT  2.4 22.259 13.608 22.741 ;
     RECT  32.736 22.693 33.48 22.741 ;
     RECT  34.8 11.699 35.112 22.741 ;
     RECT  28.896 19.955 29.712 22.981 ;
     RECT  18 22.355 21.672 23.075 ;
     RECT  32.736 22.741 35.112 23.171 ;
     RECT  14.736 22.259 16.104 23.173 ;
     RECT  18 23.075 20.952 23.173 ;
     RECT  37.728 23.125 37.752 23.221 ;
     RECT  14.736 23.173 20.952 23.317 ;
     RECT  14.592 23.317 20.952 23.363 ;
     RECT  22.8 22.355 24.408 23.411 ;
     RECT  36.336 22.165 36.6 23.411 ;
     RECT  23.568 23.411 24.408 23.603 ;
     RECT  2.304 22.741 13.608 23.701 ;
     RECT  14.592 23.363 20.616 23.701 ;
     RECT  39.312 22.307 40.512 23.987 ;
     RECT  37.632 23.221 37.752 24.085 ;
     RECT  37.632 24.085 37.992 24.131 ;
     RECT  26.208 23.365 26.232 24.277 ;
     RECT  28.896 22.981 30.216 24.469 ;
     RECT  36.384 23.411 36.6 24.469 ;
     RECT  2.304 23.701 20.616 24.563 ;
     RECT  23.568 23.603 24.312 24.563 ;
     RECT  28.176 24.469 30.216 24.563 ;
     RECT  33.024 23.171 35.112 24.563 ;
     RECT  37.728 24.131 37.992 24.659 ;
     RECT  39.648 23.987 40.512 25.091 ;
     RECT  28.176 24.563 29.832 25.139 ;
     RECT  20.592 24.563 20.616 25.187 ;
     RECT  2.304 24.563 19.128 25.525 ;
     RECT  33.072 24.563 35.112 25.669 ;
     RECT  36.144 24.469 36.6 25.669 ;
     RECT  2.304 25.525 19.32 25.715 ;
     RECT  25.584 24.277 26.232 25.715 ;
     RECT  37.968 24.659 37.992 25.715 ;
     RECT  2.304 25.715 16.92 25.763 ;
     RECT  33.072 25.669 36.6 26.147 ;
     RECT  28.896 25.139 29.832 26.149 ;
     RECT  17.904 25.715 19.32 26.243 ;
     RECT  33.072 26.147 36.024 26.243 ;
     RECT  39.888 25.091 40.512 26.243 ;
     RECT  33.072 26.243 33.72 26.291 ;
     RECT  28.512 26.149 29.832 26.341 ;
     RECT  26.208 25.715 26.232 26.531 ;
     RECT  28.512 26.341 30.024 26.579 ;
     RECT  24 24.563 24.312 26.581 ;
     RECT  18.096 26.243 19.32 26.819 ;
     RECT  27.216 26.725 27.24 27.157 ;
     RECT  28.512 26.579 29.928 27.157 ;
     RECT  2.304 25.763 16.824 27.205 ;
     RECT  18.144 26.819 19.32 27.395 ;
     RECT  27.216 27.157 29.928 27.395 ;
     RECT  21.168 26.725 21.192 27.781 ;
     RECT  23.04 26.581 24.312 27.781 ;
     RECT  27.216 27.395 27.912 27.971 ;
     RECT  2.304 27.205 16.968 28.067 ;
     RECT  16.944 28.067 16.968 28.115 ;
     RECT  33.696 26.291 33.72 28.451 ;
     RECT  26.208 28.453 26.232 28.645 ;
     RECT  27.216 27.971 27.288 28.645 ;
     RECT  26.208 28.645 27.288 28.691 ;
     RECT  21.168 27.781 21.672 28.789 ;
     RECT  34.8 26.243 36.024 28.837 ;
     RECT  23.04 27.781 25.08 29.123 ;
     RECT  26.208 28.691 27.192 29.123 ;
     RECT  29.184 27.395 29.928 29.123 ;
     RECT  17.04 28.981 17.064 29.125 ;
     RECT  23.04 29.123 24.936 29.171 ;
     RECT  27.168 29.123 27.192 29.507 ;
     RECT  2.304 28.067 15.96 29.605 ;
     RECT  16.944 29.125 17.064 29.605 ;
     RECT  20.736 28.789 21.672 29.699 ;
     RECT  34.8 28.837 36.456 29.795 ;
     RECT  18.192 27.395 19.32 29.989 ;
     RECT  20.736 29.699 21.624 29.989 ;
     RECT  29.28 29.123 29.928 30.133 ;
     RECT  2.304 29.605 17.064 30.181 ;
     RECT  18.192 29.989 21.624 30.227 ;
     RECT  23.04 29.171 24.552 30.227 ;
     RECT  28.464 30.133 29.928 30.227 ;
     RECT  23.04 30.227 24.312 30.275 ;
     RECT  2.304 30.181 17.112 30.325 ;
     RECT  18.192 30.227 21.048 30.325 ;
     RECT  28.464 30.227 29.832 30.803 ;
     RECT  23.424 30.275 24.312 30.899 ;
     RECT  2.304 30.325 21.048 31.379 ;
     RECT  20.832 31.379 21.048 31.861 ;
     RECT  24 30.899 24.312 31.861 ;
     RECT  2.304 31.379 19.368 31.955 ;
     RECT  32.592 28.789 32.616 31.955 ;
     RECT  20.832 31.861 21.432 32.195 ;
     RECT  26.736 31.189 26.76 32.195 ;
     RECT  29.4 30.803 29.832 32.245 ;
     RECT  2.304 31.955 16.536 32.531 ;
     RECT  28.704 32.245 29.832 32.531 ;
     RECT  17.616 31.955 18.912 32.771 ;
     RECT  2.4 32.531 16.536 33.107 ;
     RECT  20.4 32.437 20.424 33.107 ;
     RECT  28.704 32.531 29.712 33.107 ;
     RECT  6.096 33.107 16.536 33.155 ;
     RECT  21.408 32.195 21.432 33.155 ;
     RECT  24 31.861 24.936 33.155 ;
     RECT  6.096 33.155 15.528 33.203 ;
     RECT  16.512 33.155 16.536 33.203 ;
     RECT  18.192 32.771 18.912 33.587 ;
     RECT  2.4 33.107 5.112 33.683 ;
     RECT  2.4 33.683 4.968 33.779 ;
     RECT  6.144 33.203 15.528 33.779 ;
     RECT  31.872 32.437 31.896 33.779 ;
     RECT  34.8 29.795 35.88 33.827 ;
     RECT  24 33.155 24.312 33.925 ;
     RECT  26.784 33.877 26.808 33.925 ;
     RECT  26.784 33.925 26.952 34.163 ;
     RECT  2.4 33.779 4.488 34.259 ;
     RECT  6.624 33.779 15.528 34.259 ;
     RECT  20.448 33.541 20.472 34.259 ;
     RECT  6.624 34.259 13.656 34.307 ;
     RECT  3.984 34.259 4.488 34.355 ;
     RECT  15.312 34.259 15.528 34.355 ;
     RECT  26.928 34.163 26.952 34.355 ;
     RECT  3.984 34.355 4.008 34.403 ;
     RECT  7.344 34.307 13.656 34.403 ;
     RECT  15.504 34.355 15.528 34.403 ;
     RECT  21.648 33.589 21.672 34.403 ;
     RECT  7.344 34.403 11.688 34.451 ;
     RECT  23.856 33.925 24.312 34.451 ;
     RECT  13.2 34.403 13.656 34.499 ;
     RECT  2.4 34.259 2.712 34.569 ;
     RECT  7.584 34.451 11.688 34.569 ;
     RECT  13.2 34.499 13.512 34.569 ;
     RECT  18.6 33.587 18.912 34.569 ;
     RECT  24 34.451 24.312 34.569 ;
     RECT  29.4 33.107 29.712 34.569 ;
     RECT  34.8 33.827 35.112 34.569 ;
     RECT  40.2 26.243 40.512 34.569 ;
     RECT  2.4 34.569 2.52 34.583 ;
     RECT  7.584 34.569 7.92 34.583 ;
     RECT  13.2 34.569 13.32 34.583 ;
     RECT  18.6 34.569 18.72 34.583 ;
     RECT  24 34.569 24.12 34.583 ;
     RECT  29.4 34.569 29.52 34.583 ;
     RECT  34.8 34.569 34.92 34.583 ;
     RECT  40.2 34.569 40.32 34.583 ;
     RECT  9.024 34.569 11.688 36.035 ;
     RECT  7.584 34.583 7.608 36.083 ;
     RECT  9.024 36.035 11.208 36.56 ;
     RECT  14.136 2.197 15.36 2.245 ;
     RECT  14.184 2.245 15.36 2.485 ;
     RECT  28.2 2.581 29.4 2.963 ;
     RECT  26.76 2.821 28.176 2.963 ;
     RECT  26.76 2.963 29.4 3.301 ;
     RECT  28.152 3.301 29.4 4.501 ;
     RECT  33.624 3.397 34.704 4.453 ;
     RECT  24.312 3.443 24.648 4.453 ;
     RECT  17.064 3.877 18.432 4.933 ;
     RECT  26.688 4.115 26.736 4.453 ;
     RECT  21.144 4.163 22.176 5.459 ;
     RECT  24.312 4.453 25.68 5.509 ;
     RECT  25.704 4.453 26.736 5.605 ;
     RECT  3.48 4.501 4.896 5.605 ;
     RECT  22.2 4.501 23.664 6.035 ;
     RECT  18.912 4.547 20.256 6.565 ;
     RECT  17.112 4.933 18.432 5.029 ;
     RECT  17.16 5.029 18.432 6.035 ;
     RECT  20.376 5.459 22.176 6.035 ;
     RECT  24.408 5.509 25.68 5.651 ;
     RECT  24.408 5.651 26.208 6.325 ;
     RECT  33.624 5.699 34.8 8.771 ;
     RECT  26.472 5.747 28.128 6.659 ;
     RECT  39.936 5.747 40.2 6.709 ;
     RECT  28.152 5.795 29.4 6.659 ;
     RECT  33.264 5.891 33.6 7.381 ;
     RECT  17.16 6.035 18.6 6.899 ;
     RECT  20.376 6.035 21.576 6.805 ;
     RECT  25.128 6.325 26.208 6.853 ;
     RECT  26.472 6.659 27.144 7.237 ;
     RECT  29.28 6.659 29.4 6.901 ;
     RECT  20.376 6.805 21.552 7.187 ;
     RECT  16.392 6.899 18.6 7.189 ;
     RECT  2.712 6.947 3.696 8.437 ;
     RECT  16.392 7.189 17.808 7.859 ;
     RECT  24.312 7.475 25.344 8.771 ;
     RECT  25.368 7.667 26.448 8.771 ;
     RECT  16.248 7.859 17.808 8.437 ;
     RECT  29.712 8.003 30.816 10.307 ;
     RECT  16.248 8.437 17.664 9.299 ;
     RECT  24.312 8.771 24.648 9.061 ;
     RECT  33.288 8.771 34.8 10.355 ;
     RECT  21.552 9.155 22.176 10.213 ;
     RECT  26.808 9.251 27.144 10.645 ;
     RECT  15.864 9.299 17.664 9.683 ;
     RECT  4.104 9.635 5.616 10.789 ;
     RECT  15.768 9.683 17.664 9.779 ;
     RECT  15.768 9.779 18.48 10.741 ;
     RECT  24.312 9.779 24.648 10.741 ;
     RECT  29.712 10.307 30.12 10.453 ;
     RECT  29.832 10.453 30.12 11.125 ;
     RECT  28.752 10.643 28.755 11.029 ;
     RECT  16.2 10.741 18.48 10.981 ;
     RECT  24.936 10.741 26.448 10.933 ;
     RECT  4.584 10.789 5.616 11.651 ;
     RECT  2.712 10.931 3.888 14.629 ;
     RECT  24.936 10.933 25.92 11.747 ;
     RECT  16.2 10.981 17.616 11.317 ;
     RECT  27.336 11.029 28.755 13.715 ;
     RECT  16.584 11.317 17.616 11.365 ;
     RECT  17.304 11.459 18.48 14.773 ;
     RECT  4.584 11.651 6.576 11.797 ;
     RECT  24.648 11.747 25.92 16.019 ;
     RECT  5.496 11.797 6.576 13.333 ;
     RECT  18.912 13.045 19.968 13.525 ;
     RECT  21.528 13.139 22.344 13.571 ;
     RECT  14.616 13.187 15.648 15.445 ;
     RECT  21.48 13.571 22.344 14.197 ;
     RECT  21.48 14.197 22.704 14.627 ;
     RECT  22.728 14.197 24 15.107 ;
     RECT  6.12 14.243 7.104 17.077 ;
     RECT  18.912 14.387 20.16 15.635 ;
     RECT  21.336 14.627 22.704 15.107 ;
     RECT  16.008 14.725 17.28 16.933 ;
     RECT  17.304 14.773 18.432 15.829 ;
     RECT  21.336 15.107 24 15.491 ;
     RECT  22.704 15.491 24 16.309 ;
     RECT  18.912 15.635 20.544 15.731 ;
     RECT  18.912 15.731 19.32 15.781 ;
     RECT  17.304 15.829 18.384 16.069 ;
     RECT  22.728 16.309 24 17.029 ;
     RECT  16.056 16.933 17.28 16.981 ;
     RECT  22.776 17.029 24 17.605 ;
     RECT  15.816 17.651 16.992 19.333 ;
     RECT  15.96 19.333 16.992 20.725 ;
     RECT  20.376 20.725 21.6 22.261 ;
     RECT  17.016 21.155 18 21.251 ;
     RECT  32.736 21.155 32.76 22.165 ;
     RECT  16.68 21.251 18 22.211 ;
     RECT  35.112 21.253 36.384 22.117 ;
     RECT  38.76 21.397 39.744 22.117 ;
     RECT  35.112 22.117 36.336 23.411 ;
     RECT  16.104 22.211 18 23.173 ;
     RECT  13.608 22.259 14.736 23.317 ;
     RECT  21.672 22.355 22.8 23.075 ;
     RECT  33.48 22.693 34.8 22.741 ;
     RECT  36.6 23.125 37.728 23.221 ;
     RECT  36.6 23.221 37.632 24.131 ;
     RECT  13.608 23.317 14.592 23.701 ;
     RECT  35.112 23.411 36.384 24.469 ;
     RECT  24.312 23.603 24.408 24.277 ;
     RECT  36.6 24.131 37.728 24.659 ;
     RECT  24.312 24.277 25.584 25.715 ;
     RECT  35.112 24.469 36.144 25.669 ;
     RECT  19.128 24.563 20.592 25.187 ;
     RECT  36.6 24.659 37.968 25.715 ;
     RECT  28.512 25.139 28.896 26.149 ;
     RECT  19.128 25.187 19.32 25.525 ;
     RECT  16.92 25.715 17.904 25.763 ;
     RECT  16.824 25.763 17.904 26.243 ;
     RECT  16.824 26.243 18.096 26.819 ;
     RECT  33.72 26.243 34.8 28.451 ;
     RECT  27.24 26.725 28.512 27.157 ;
     RECT  16.824 26.819 18.144 27.205 ;
     RECT  16.968 27.205 18.144 27.395 ;
     RECT  16.968 27.395 18.192 28.115 ;
     RECT  27.912 27.395 29.184 27.971 ;
     RECT  21.672 27.781 23.04 29.699 ;
     RECT  15.96 28.067 16.944 28.115 ;
     RECT  15.96 28.115 18.192 28.981 ;
     RECT  25.08 28.453 26.208 29.123 ;
     RECT  26.232 28.453 27.216 28.645 ;
     RECT  19.32 28.789 20.736 29.989 ;
     RECT  15.96 28.981 17.04 29.125 ;
     RECT  17.064 28.981 18.192 30.181 ;
     RECT  29.184 29.123 29.28 30.133 ;
     RECT  15.96 29.125 16.944 29.605 ;
     RECT  21.624 29.699 23.04 30.227 ;
     RECT  17.112 30.181 18.192 30.325 ;
     RECT  28.704 30.803 29.4 32.245 ;
     RECT  19.368 31.379 20.832 31.955 ;
     RECT  16.536 31.955 17.616 32.771 ;
     RECT  18.912 31.955 20.832 32.195 ;
     RECT  18.912 32.195 21.408 32.437 ;
     RECT  18.912 32.437 20.4 33.107 ;
     RECT  20.424 32.437 21.408 33.107 ;
     RECT  5.112 33.107 6.096 33.203 ;
     RECT  20.448 33.107 21.408 33.155 ;
     RECT  15.528 33.155 16.512 33.203 ;
     RECT  20.448 33.155 21.432 33.541 ;
     RECT  5.112 33.203 6.144 33.683 ;
     RECT  20.472 33.541 21.432 33.589 ;
     RECT  20.472 33.589 21.648 34.259 ;
     RECT  4.968 33.683 6.144 33.779 ;
     RECT  2.712 34.259 3.984 34.403 ;
     RECT  11.688 34.403 13.2 34.583 ;
     RECT  7.92 34.569 9.024 34.583 ;
     RECT  7.608 34.583 9.024 36.083 ;
  END
END ot_s81_markov_chunk1_native
END LIBRARY
